VERSION 5.8 ;
BUSBITCHARS "[]" ;
DIVIDERCHAR "/" ;
UNITS
    DATABASE MICRONS 1000 ;
END UNITS

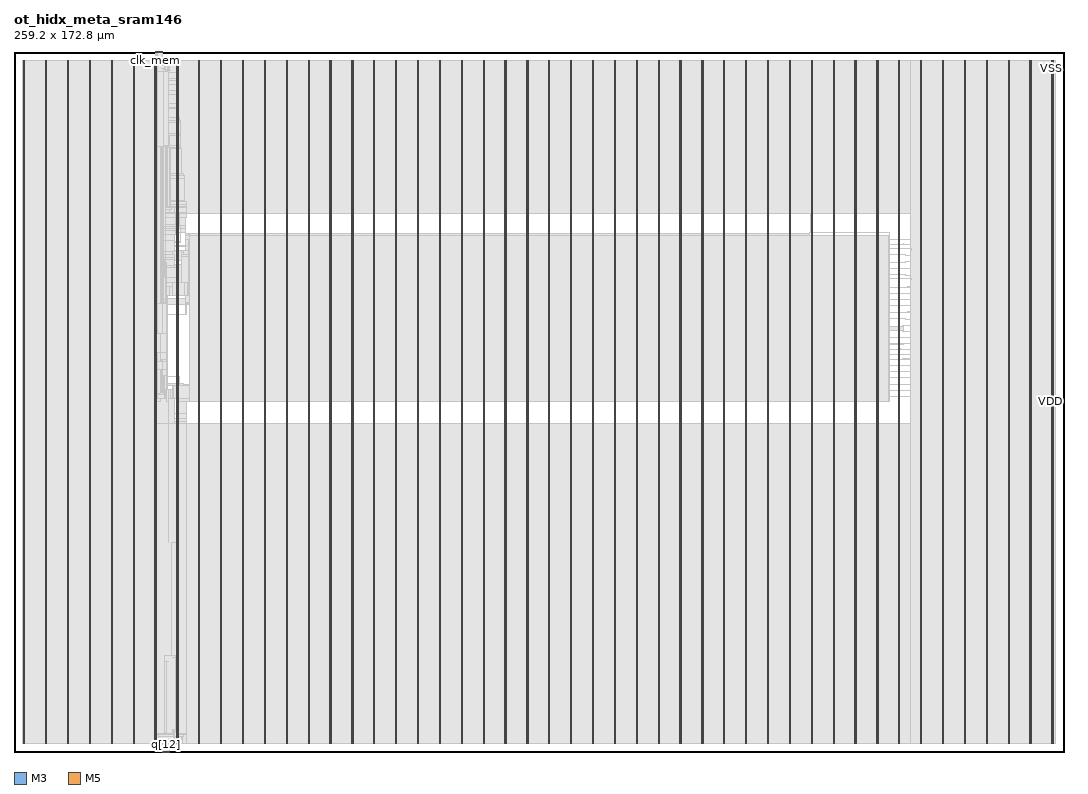
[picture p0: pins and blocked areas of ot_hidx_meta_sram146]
MACRO ot_hidx_meta_sram146
  FOREIGN ot_hidx_meta_sram146 0 0 ;
  CLASS BLOCK ;
  SIZE 259.2 BY 172.8 ;
  PIN clk
    DIRECTION INPUT ;
    USE SIGNAL ;
    PORT
      LAYER M3 ;
        RECT  34.884 172.763 34.902 172.8 ;
    END
  END clk
  PIN clk_mem
    DIRECTION INPUT ;
    USE SIGNAL ;
    PORT
      LAYER M3 ;
        RECT  34.956 172.763 34.974 172.8 ;
    END
  END clk_mem
  PIN d[0]
    DIRECTION INPUT ;
    USE SIGNAL ;
    PORT
      LAYER M3 ;
        RECT  35.028 172.763 35.046 172.8 ;
    END
  END d[0]
  PIN d[10]
    DIRECTION INPUT ;
    USE SIGNAL ;
    PORT
      LAYER M3 ;
        RECT  35.748 172.763 35.766 172.8 ;
    END
  END d[10]
  PIN d[11]
    DIRECTION INPUT ;
    USE SIGNAL ;
    PORT
      LAYER M3 ;
        RECT  35.82 172.763 35.838 172.8 ;
    END
  END d[11]
  PIN d[12]
    DIRECTION INPUT ;
    USE SIGNAL ;
    PORT
      LAYER M3 ;
        RECT  35.892 172.763 35.91 172.8 ;
    END
  END d[12]
  PIN d[13]
    DIRECTION INPUT ;
    USE SIGNAL ;
    PORT
      LAYER M3 ;
        RECT  35.964 172.763 35.982 172.8 ;
    END
  END d[13]
  PIN d[14]
    DIRECTION INPUT ;
    USE SIGNAL ;
    PORT
      LAYER M3 ;
        RECT  36.036 172.763 36.054 172.8 ;
    END
  END d[14]
  PIN d[15]
    DIRECTION INPUT ;
    USE SIGNAL ;
    PORT
      LAYER M3 ;
        RECT  36.108 172.763 36.126 172.8 ;
    END
  END d[15]
  PIN d[16]
    DIRECTION INPUT ;
    USE SIGNAL ;
    PORT
      LAYER M3 ;
        RECT  36.18 172.763 36.198 172.8 ;
    END
  END d[16]
  PIN d[17]
    DIRECTION INPUT ;
    USE SIGNAL ;
    PORT
      LAYER M3 ;
        RECT  36.252 172.763 36.27 172.8 ;
    END
  END d[17]
  PIN d[18]
    DIRECTION INPUT ;
    USE SIGNAL ;
    PORT
      LAYER M3 ;
        RECT  36.324 172.763 36.342 172.8 ;
    END
  END d[18]
  PIN d[19]
    DIRECTION INPUT ;
    USE SIGNAL ;
    PORT
      LAYER M3 ;
        RECT  36.396 172.763 36.414 172.8 ;
    END
  END d[19]
  PIN d[1]
    DIRECTION INPUT ;
    USE SIGNAL ;
    PORT
      LAYER M3 ;
        RECT  35.1 172.763 35.118 172.8 ;
    END
  END d[1]
  PIN d[20]
    DIRECTION INPUT ;
    USE SIGNAL ;
    PORT
      LAYER M3 ;
        RECT  36.468 172.763 36.486 172.8 ;
    END
  END d[20]
  PIN d[21]
    DIRECTION INPUT ;
    USE SIGNAL ;
    PORT
      LAYER M3 ;
        RECT  36.54 172.763 36.558 172.8 ;
    END
  END d[21]
  PIN d[22]
    DIRECTION INPUT ;
    USE SIGNAL ;
    PORT
      LAYER M3 ;
        RECT  36.612 172.763 36.63 172.8 ;
    END
  END d[22]
  PIN d[23]
    DIRECTION INPUT ;
    USE SIGNAL ;
    PORT
      LAYER M3 ;
        RECT  36.684 172.763 36.702 172.8 ;
    END
  END d[23]
  PIN d[24]
    DIRECTION INPUT ;
    USE SIGNAL ;
    PORT
      LAYER M3 ;
        RECT  36.756 172.763 36.774 172.8 ;
    END
  END d[24]
  PIN d[2]
    DIRECTION INPUT ;
    USE SIGNAL ;
    PORT
      LAYER M3 ;
        RECT  35.172 172.763 35.19 172.8 ;
    END
  END d[2]
  PIN d[3]
    DIRECTION INPUT ;
    USE SIGNAL ;
    PORT
      LAYER M3 ;
        RECT  35.244 172.763 35.262 172.8 ;
    END
  END d[3]
  PIN d[4]
    DIRECTION INPUT ;
    USE SIGNAL ;
    PORT
      LAYER M3 ;
        RECT  35.316 172.763 35.334 172.8 ;
    END
  END d[4]
  PIN d[5]
    DIRECTION INPUT ;
    USE SIGNAL ;
    PORT
      LAYER M3 ;
        RECT  35.388 172.763 35.406 172.8 ;
    END
  END d[5]
  PIN d[6]
    DIRECTION INPUT ;
    USE SIGNAL ;
    PORT
      LAYER M3 ;
        RECT  35.46 172.763 35.478 172.8 ;
    END
  END d[6]
  PIN d[7]
    DIRECTION INPUT ;
    USE SIGNAL ;
    PORT
      LAYER M3 ;
        RECT  35.532 172.763 35.55 172.8 ;
    END
  END d[7]
  PIN d[8]
    DIRECTION INPUT ;
    USE SIGNAL ;
    PORT
      LAYER M3 ;
        RECT  35.604 172.763 35.622 172.8 ;
    END
  END d[8]
  PIN d[9]
    DIRECTION INPUT ;
    USE SIGNAL ;
    PORT
      LAYER M3 ;
        RECT  35.676 172.763 35.694 172.8 ;
    END
  END d[9]
  PIN q[0]
    DIRECTION OUTPUT ;
    USE SIGNAL ;
    PORT
      LAYER M3 ;
        RECT  36.54 0 36.558 0.037 ;
    END
  END q[0]
  PIN q[10]
    DIRECTION OUTPUT ;
    USE SIGNAL ;
    PORT
      LAYER M3 ;
        RECT  37.26 0 37.278 0.037 ;
    END
  END q[10]
  PIN q[11]
    DIRECTION OUTPUT ;
    USE SIGNAL ;
    PORT
      LAYER M3 ;
        RECT  37.332 0 37.35 0.037 ;
    END
  END q[11]
  PIN q[12]
    DIRECTION OUTPUT ;
    USE SIGNAL ;
    PORT
      LAYER M3 ;
        RECT  37.404 0 37.422 0.037 ;
    END
  END q[12]
  PIN q[13]
    DIRECTION OUTPUT ;
    USE SIGNAL ;
    PORT
      LAYER M3 ;
        RECT  37.476 0 37.494 0.037 ;
    END
  END q[13]
  PIN q[14]
    DIRECTION OUTPUT ;
    USE SIGNAL ;
    PORT
      LAYER M3 ;
        RECT  37.548 0 37.566 0.037 ;
    END
  END q[14]
  PIN q[15]
    DIRECTION OUTPUT ;
    USE SIGNAL ;
    PORT
      LAYER M3 ;
        RECT  37.62 0 37.638 0.037 ;
    END
  END q[15]
  PIN q[16]
    DIRECTION OUTPUT ;
    USE SIGNAL ;
    PORT
      LAYER M3 ;
        RECT  37.692 0 37.71 0.037 ;
    END
  END q[16]
  PIN q[17]
    DIRECTION OUTPUT ;
    USE SIGNAL ;
    PORT
      LAYER M3 ;
        RECT  37.764 0 37.782 0.037 ;
    END
  END q[17]
  PIN q[18]
    DIRECTION OUTPUT ;
    USE SIGNAL ;
    PORT
      LAYER M3 ;
        RECT  37.836 0 37.854 0.037 ;
    END
  END q[18]
  PIN q[19]
    DIRECTION OUTPUT ;
    USE SIGNAL ;
    PORT
      LAYER M3 ;
        RECT  37.908 0 37.926 0.037 ;
    END
  END q[19]
  PIN q[1]
    DIRECTION OUTPUT ;
    USE SIGNAL ;
    PORT
      LAYER M3 ;
        RECT  36.612 0 36.63 0.037 ;
    END
  END q[1]
  PIN q[20]
    DIRECTION OUTPUT ;
    USE SIGNAL ;
    PORT
      LAYER M3 ;
        RECT  37.98 0 37.998 0.037 ;
    END
  END q[20]
  PIN q[21]
    DIRECTION OUTPUT ;
    USE SIGNAL ;
    PORT
      LAYER M3 ;
        RECT  38.052 0 38.07 0.037 ;
    END
  END q[21]
  PIN q[22]
    DIRECTION OUTPUT ;
    USE SIGNAL ;
    PORT
      LAYER M3 ;
        RECT  38.124 0 38.142 0.037 ;
    END
  END q[22]
  PIN q[23]
    DIRECTION OUTPUT ;
    USE SIGNAL ;
    PORT
      LAYER M3 ;
        RECT  38.196 0 38.214 0.037 ;
    END
  END q[23]
  PIN q[24]
    DIRECTION OUTPUT ;
    USE SIGNAL ;
    PORT
      LAYER M3 ;
        RECT  38.268 0 38.286 0.037 ;
    END
  END q[24]
  PIN q[2]
    DIRECTION OUTPUT ;
    USE SIGNAL ;
    PORT
      LAYER M3 ;
        RECT  36.684 0 36.702 0.037 ;
    END
  END q[2]
  PIN q[3]
    DIRECTION OUTPUT ;
    USE SIGNAL ;
    PORT
      LAYER M3 ;
        RECT  36.756 0 36.774 0.037 ;
    END
  END q[3]
  PIN q[4]
    DIRECTION OUTPUT ;
    USE SIGNAL ;
    PORT
      LAYER M3 ;
        RECT  36.828 0 36.846 0.037 ;
    END
  END q[4]
  PIN q[5]
    DIRECTION OUTPUT ;
    USE SIGNAL ;
    PORT
      LAYER M3 ;
        RECT  36.9 0 36.918 0.037 ;
    END
  END q[5]
  PIN q[6]
    DIRECTION OUTPUT ;
    USE SIGNAL ;
    PORT
      LAYER M3 ;
        RECT  36.972 0 36.99 0.037 ;
    END
  END q[6]
  PIN q[7]
    DIRECTION OUTPUT ;
    USE SIGNAL ;
    PORT
      LAYER M3 ;
        RECT  37.044 0 37.062 0.037 ;
    END
  END q[7]
  PIN q[8]
    DIRECTION OUTPUT ;
    USE SIGNAL ;
    PORT
      LAYER M3 ;
        RECT  37.116 0 37.134 0.037 ;
    END
  END q[8]
  PIN q[9]
    DIRECTION OUTPUT ;
    USE SIGNAL ;
    PORT
      LAYER M3 ;
        RECT  37.188 0 37.206 0.037 ;
    END
  END q[9]
  PIN VDD
    DIRECTION INOUT ;
    USE POWER ;
    PORT
      LAYER M5 ;
        RECT  256.392 2.151 256.512 170.649 ;
        RECT  250.992 2.151 251.112 170.649 ;
        RECT  245.592 2.151 245.712 170.649 ;
        RECT  240.192 2.151 240.312 170.649 ;
        RECT  234.792 2.151 234.912 170.649 ;
        RECT  229.392 2.151 229.512 170.649 ;
        RECT  223.992 2.151 224.112 170.649 ;
        RECT  218.592 2.151 218.712 170.649 ;
        RECT  213.192 2.151 213.312 170.649 ;
        RECT  207.792 2.151 207.912 170.649 ;
        RECT  202.392 2.151 202.512 170.649 ;
        RECT  196.992 2.151 197.112 170.649 ;
        RECT  191.592 2.151 191.712 170.649 ;
        RECT  186.192 2.151 186.312 170.649 ;
        RECT  180.792 2.151 180.912 170.649 ;
        RECT  175.392 2.151 175.512 170.649 ;
        RECT  169.992 2.151 170.112 170.649 ;
        RECT  164.592 2.151 164.712 170.649 ;
        RECT  159.192 2.151 159.312 170.649 ;
        RECT  153.792 2.151 153.912 170.649 ;
        RECT  148.392 2.151 148.512 170.649 ;
        RECT  142.992 2.151 143.112 170.649 ;
        RECT  137.592 2.151 137.712 170.649 ;
        RECT  132.192 2.151 132.312 170.649 ;
        RECT  126.792 2.151 126.912 170.649 ;
        RECT  121.392 2.151 121.512 170.649 ;
        RECT  115.992 2.151 116.112 170.649 ;
        RECT  110.592 2.151 110.712 170.649 ;
        RECT  105.192 2.151 105.312 170.649 ;
        RECT  99.792 2.151 99.912 170.649 ;
        RECT  94.392 2.151 94.512 170.649 ;
        RECT  88.992 2.151 89.112 170.649 ;
        RECT  83.592 2.151 83.712 170.649 ;
        RECT  78.192 2.151 78.312 170.649 ;
        RECT  72.792 2.151 72.912 170.649 ;
        RECT  67.392 2.151 67.512 170.649 ;
        RECT  61.992 2.151 62.112 170.649 ;
        RECT  56.592 2.151 56.712 170.649 ;
        RECT  51.192 2.151 51.312 170.649 ;
        RECT  45.792 2.151 45.912 170.649 ;
        RECT  40.392 2.151 40.512 170.649 ;
        RECT  34.992 2.151 35.112 170.649 ;
        RECT  29.592 2.151 29.712 170.649 ;
        RECT  24.192 2.151 24.312 170.649 ;
        RECT  18.792 2.151 18.912 170.649 ;
        RECT  13.392 2.151 13.512 170.649 ;
        RECT  7.992 2.151 8.112 170.649 ;
        RECT  2.592 2.151 2.712 170.649 ;
    END
  END VDD
  PIN VSS
    DIRECTION INOUT ;
    USE GROUND ;
    PORT
      LAYER M5 ;
        RECT  256.2 2.137 256.32 170.663 ;
        RECT  250.8 2.137 250.92 170.663 ;
        RECT  245.4 2.137 245.52 170.663 ;
        RECT  240 2.137 240.12 170.663 ;
        RECT  234.6 2.137 234.72 170.663 ;
        RECT  229.2 2.137 229.32 170.663 ;
        RECT  223.8 2.137 223.92 170.663 ;
        RECT  218.4 2.137 218.52 170.663 ;
        RECT  213 2.137 213.12 170.663 ;
        RECT  207.6 2.137 207.72 170.663 ;
        RECT  202.2 2.137 202.32 170.663 ;
        RECT  196.8 2.137 196.92 170.663 ;
        RECT  191.4 2.137 191.52 170.663 ;
        RECT  186 2.137 186.12 170.663 ;
        RECT  180.6 2.137 180.72 170.663 ;
        RECT  175.2 2.137 175.32 170.663 ;
        RECT  169.8 2.137 169.92 170.663 ;
        RECT  164.4 2.137 164.52 170.663 ;
        RECT  159 2.137 159.12 170.663 ;
        RECT  153.6 2.137 153.72 170.663 ;
        RECT  148.2 2.137 148.32 170.663 ;
        RECT  142.8 2.137 142.92 170.663 ;
        RECT  137.4 2.137 137.52 170.663 ;
        RECT  132 2.137 132.12 170.663 ;
        RECT  126.6 2.137 126.72 170.663 ;
        RECT  121.2 2.137 121.32 170.663 ;
        RECT  115.8 2.137 115.92 170.663 ;
        RECT  110.4 2.137 110.52 170.663 ;
        RECT  105 2.137 105.12 170.663 ;
        RECT  99.6 2.137 99.72 170.663 ;
        RECT  94.2 2.137 94.32 170.663 ;
        RECT  88.8 2.137 88.92 170.663 ;
        RECT  83.4 2.137 83.52 170.663 ;
        RECT  78 2.137 78.12 170.663 ;
        RECT  72.6 2.137 72.72 170.663 ;
        RECT  67.2 2.137 67.32 170.663 ;
        RECT  61.8 2.137 61.92 170.663 ;
        RECT  56.4 2.137 56.52 170.663 ;
        RECT  51 2.137 51.12 170.663 ;
        RECT  45.6 2.137 45.72 170.663 ;
        RECT  40.2 2.137 40.32 170.663 ;
        RECT  34.8 2.137 34.92 170.663 ;
        RECT  29.4 2.137 29.52 170.663 ;
        RECT  24 2.137 24.12 170.663 ;
        RECT  18.6 2.137 18.72 170.663 ;
        RECT  13.2 2.137 13.32 170.663 ;
        RECT  7.8 2.137 7.92 170.663 ;
        RECT  2.4 2.137 2.52 170.663 ;
    END
  END VSS
  # OT_OBS_CLOSED layer=M5 d_um=1.536 added=8
  OBS
    LAYER RVTN ;
     RECT  2.16 2.16 257.04 2.295 ;
     RECT  2.16 2.565 257.04 2.835 ;
     RECT  2.16 3.105 257.04 3.375 ;
     RECT  2.16 3.645 257.04 3.915 ;
     RECT  2.16 4.185 257.04 4.455 ;
     RECT  2.16 4.725 257.04 4.995 ;
     RECT  2.16 5.265 257.04 5.535 ;
     RECT  2.16 5.805 257.04 6.075 ;
     RECT  2.16 6.345 257.04 6.615 ;
     RECT  2.16 6.885 257.04 7.155 ;
     RECT  2.16 7.425 257.04 7.695 ;
     RECT  2.16 7.965 257.04 8.235 ;
     RECT  2.16 8.505 257.04 8.775 ;
     RECT  2.16 9.045 257.04 9.315 ;
     RECT  2.16 9.585 257.04 9.855 ;
     RECT  2.16 10.125 257.04 10.395 ;
     RECT  2.16 10.665 257.04 10.935 ;
     RECT  2.16 11.205 257.04 11.475 ;
     RECT  2.16 11.745 257.04 12.015 ;
     RECT  2.16 12.285 257.04 12.555 ;
     RECT  2.16 12.825 257.04 13.095 ;
     RECT  2.16 13.365 257.04 13.635 ;
     RECT  2.16 13.905 257.04 14.175 ;
     RECT  2.16 14.445 257.04 14.715 ;
     RECT  2.16 14.985 257.04 15.255 ;
     RECT  2.16 15.525 257.04 15.795 ;
     RECT  2.16 16.065 257.04 16.335 ;
     RECT  2.16 16.605 257.04 16.875 ;
     RECT  2.16 17.145 257.04 17.415 ;
     RECT  2.16 17.685 257.04 17.955 ;
     RECT  2.16 18.225 257.04 18.495 ;
     RECT  2.16 18.765 257.04 19.035 ;
     RECT  2.16 19.305 257.04 19.575 ;
     RECT  2.16 19.845 257.04 20.115 ;
     RECT  2.16 20.385 257.04 20.655 ;
     RECT  2.16 20.925 257.04 21.195 ;
     RECT  2.16 21.465 257.04 21.735 ;
     RECT  2.16 22.005 257.04 22.275 ;
     RECT  2.16 22.545 257.04 22.815 ;
     RECT  2.16 23.085 257.04 23.355 ;
     RECT  2.16 23.625 257.04 23.895 ;
     RECT  2.16 24.165 257.04 24.435 ;
     RECT  2.16 24.705 257.04 24.975 ;
     RECT  2.16 25.245 257.04 25.515 ;
     RECT  2.16 25.785 257.04 26.055 ;
     RECT  2.16 26.325 257.04 26.595 ;
     RECT  2.16 26.865 257.04 27.135 ;
     RECT  2.16 27.405 257.04 27.675 ;
     RECT  2.16 27.945 257.04 28.215 ;
     RECT  2.16 28.485 257.04 28.755 ;
     RECT  2.16 29.025 257.04 29.295 ;
     RECT  2.16 29.565 257.04 29.835 ;
     RECT  2.16 30.105 257.04 30.375 ;
     RECT  2.16 30.645 257.04 30.915 ;
     RECT  2.16 31.185 257.04 31.455 ;
     RECT  2.16 31.725 257.04 31.995 ;
     RECT  2.16 32.265 257.04 32.535 ;
     RECT  2.16 32.805 257.04 33.075 ;
     RECT  2.16 33.345 257.04 33.615 ;
     RECT  2.16 33.885 257.04 34.155 ;
     RECT  2.16 34.425 257.04 34.695 ;
     RECT  2.16 34.965 257.04 35.235 ;
     RECT  2.16 35.505 257.04 35.775 ;
     RECT  2.16 36.045 257.04 36.315 ;
     RECT  2.16 36.585 257.04 36.855 ;
     RECT  2.16 37.125 257.04 37.395 ;
     RECT  2.16 37.665 257.04 37.935 ;
     RECT  2.16 38.205 257.04 38.475 ;
     RECT  2.16 38.745 257.04 39.015 ;
     RECT  2.16 39.285 257.04 39.555 ;
     RECT  2.16 39.825 257.04 40.095 ;
     RECT  2.16 40.365 257.04 40.635 ;
     RECT  2.16 40.905 257.04 41.175 ;
     RECT  2.16 41.445 257.04 41.715 ;
     RECT  2.16 41.985 257.04 42.255 ;
     RECT  2.16 42.525 257.04 42.795 ;
     RECT  2.16 43.065 257.04 43.335 ;
     RECT  2.16 43.605 257.04 43.875 ;
     RECT  2.16 44.145 257.04 44.415 ;
     RECT  2.16 44.685 257.04 44.955 ;
     RECT  2.16 45.225 257.04 45.495 ;
     RECT  2.16 45.765 257.04 46.035 ;
     RECT  2.16 46.305 257.04 46.575 ;
     RECT  2.16 46.845 257.04 47.115 ;
     RECT  2.16 47.385 257.04 47.655 ;
     RECT  2.16 47.925 257.04 48.195 ;
     RECT  2.16 48.465 257.04 48.735 ;
     RECT  2.16 49.005 257.04 49.275 ;
     RECT  2.16 49.545 257.04 49.815 ;
     RECT  2.16 50.085 257.04 50.355 ;
     RECT  2.16 50.625 257.04 50.895 ;
     RECT  2.16 51.165 257.04 51.435 ;
     RECT  2.16 51.705 257.04 51.975 ;
     RECT  2.16 52.245 257.04 52.515 ;
     RECT  2.16 52.785 257.04 53.055 ;
     RECT  2.16 53.325 257.04 53.595 ;
     RECT  2.16 53.865 257.04 54.135 ;
     RECT  2.16 54.405 257.04 54.675 ;
     RECT  2.16 54.945 257.04 55.215 ;
     RECT  2.16 55.485 257.04 55.755 ;
     RECT  2.16 56.025 257.04 56.295 ;
     RECT  2.16 56.565 257.04 56.835 ;
     RECT  2.16 57.105 257.04 57.375 ;
     RECT  2.16 57.645 257.04 57.915 ;
     RECT  2.16 58.185 257.04 58.455 ;
     RECT  2.16 58.725 257.04 58.995 ;
     RECT  2.16 59.265 257.04 59.535 ;
     RECT  2.16 59.805 257.04 60.075 ;
     RECT  2.16 60.345 257.04 60.615 ;
     RECT  2.16 60.885 257.04 61.155 ;
     RECT  2.16 61.425 257.04 61.695 ;
     RECT  2.16 61.965 257.04 62.235 ;
     RECT  2.16 62.505 257.04 62.775 ;
     RECT  2.16 63.045 257.04 63.315 ;
     RECT  2.16 63.585 257.04 63.855 ;
     RECT  2.16 64.125 257.04 64.395 ;
     RECT  2.16 64.665 257.04 64.935 ;
     RECT  2.16 65.205 257.04 65.475 ;
     RECT  2.16 65.745 257.04 66.015 ;
     RECT  2.16 66.285 257.04 66.555 ;
     RECT  2.16 66.825 257.04 67.095 ;
     RECT  2.16 67.365 257.04 67.635 ;
     RECT  2.16 67.905 257.04 68.175 ;
     RECT  2.16 68.445 257.04 68.715 ;
     RECT  2.16 68.985 257.04 69.255 ;
     RECT  2.16 69.525 257.04 69.795 ;
     RECT  2.16 70.065 257.04 70.335 ;
     RECT  2.16 70.605 257.04 70.875 ;
     RECT  2.16 71.145 257.04 71.415 ;
     RECT  2.16 71.685 257.04 71.955 ;
     RECT  2.16 72.225 257.04 72.495 ;
     RECT  2.16 72.765 257.04 73.035 ;
     RECT  2.16 73.305 257.04 73.575 ;
     RECT  2.16 73.845 257.04 74.115 ;
     RECT  2.16 74.385 257.04 74.655 ;
     RECT  2.16 74.925 257.04 75.195 ;
     RECT  2.16 75.465 257.04 75.735 ;
     RECT  2.16 76.005 257.04 76.275 ;
     RECT  2.16 76.545 257.04 76.815 ;
     RECT  2.16 77.085 257.04 77.355 ;
     RECT  2.16 77.625 257.04 77.895 ;
     RECT  2.16 78.165 257.04 78.435 ;
     RECT  2.16 78.705 257.04 78.975 ;
     RECT  2.16 79.245 257.04 79.515 ;
     RECT  2.16 79.785 257.04 80.055 ;
     RECT  2.16 80.325 257.04 80.595 ;
     RECT  2.16 80.865 257.04 81 ;
     RECT  2.16 81 37.8 81.135 ;
     RECT  221.4 81 257.04 81.135 ;
     RECT  2.16 81.405 37.8 81.675 ;
     RECT  221.4 81.405 257.04 81.675 ;
     RECT  2.16 81.945 37.8 82.215 ;
     RECT  221.4 81.945 257.04 82.215 ;
     RECT  2.16 82.485 37.8 82.755 ;
     RECT  221.4 82.485 257.04 82.755 ;
     RECT  2.16 83.025 37.8 83.295 ;
     RECT  221.4 83.025 257.04 83.295 ;
     RECT  2.16 83.565 37.8 83.835 ;
     RECT  221.4 83.565 257.04 83.835 ;
     RECT  2.16 84.105 37.8 84.375 ;
     RECT  221.4 84.105 257.04 84.375 ;
     RECT  2.16 84.645 37.8 84.915 ;
     RECT  221.4 84.645 257.04 84.915 ;
     RECT  2.16 85.185 37.8 85.455 ;
     RECT  221.4 85.185 257.04 85.455 ;
     RECT  2.16 85.725 37.8 85.995 ;
     RECT  221.4 85.725 257.04 85.995 ;
     RECT  2.16 86.265 37.8 86.535 ;
     RECT  221.4 86.265 257.04 86.535 ;
     RECT  2.16 86.805 37.8 87.075 ;
     RECT  221.4 86.805 257.04 87.075 ;
     RECT  2.16 87.345 37.8 87.615 ;
     RECT  221.4 87.345 257.04 87.615 ;
     RECT  2.16 87.885 37.8 88.155 ;
     RECT  221.4 87.885 257.04 88.155 ;
     RECT  2.16 88.425 37.8 88.695 ;
     RECT  221.4 88.425 257.04 88.695 ;
     RECT  2.16 88.965 37.8 89.235 ;
     RECT  221.4 88.965 257.04 89.235 ;
     RECT  2.16 89.505 37.8 89.775 ;
     RECT  221.4 89.505 257.04 89.775 ;
     RECT  2.16 90.045 37.8 90.315 ;
     RECT  221.4 90.045 257.04 90.315 ;
     RECT  2.16 90.585 37.8 90.855 ;
     RECT  221.4 90.585 257.04 90.855 ;
     RECT  2.16 91.125 37.8 91.395 ;
     RECT  221.4 91.125 257.04 91.395 ;
     RECT  2.16 91.665 37.8 91.935 ;
     RECT  221.4 91.665 257.04 91.935 ;
     RECT  2.16 92.205 37.8 92.475 ;
     RECT  221.4 92.205 257.04 92.475 ;
     RECT  2.16 92.745 37.8 93.015 ;
     RECT  221.4 92.745 257.04 93.015 ;
     RECT  2.16 93.285 37.8 93.555 ;
     RECT  221.4 93.285 257.04 93.555 ;
     RECT  2.16 93.825 37.8 94.095 ;
     RECT  221.4 93.825 257.04 94.095 ;
     RECT  2.16 94.365 37.8 94.635 ;
     RECT  221.4 94.365 257.04 94.635 ;
     RECT  2.16 94.905 37.8 95.175 ;
     RECT  221.4 94.905 257.04 95.175 ;
     RECT  2.16 95.445 37.8 95.715 ;
     RECT  221.4 95.445 257.04 95.715 ;
     RECT  2.16 95.985 37.8 96.255 ;
     RECT  221.4 95.985 257.04 96.255 ;
     RECT  2.16 96.525 37.8 96.795 ;
     RECT  221.4 96.525 257.04 96.795 ;
     RECT  2.16 97.065 37.8 97.335 ;
     RECT  221.4 97.065 257.04 97.335 ;
     RECT  2.16 97.605 37.8 97.875 ;
     RECT  221.4 97.605 257.04 97.875 ;
     RECT  2.16 98.145 37.8 98.415 ;
     RECT  221.4 98.145 257.04 98.415 ;
     RECT  2.16 98.685 37.8 98.955 ;
     RECT  221.4 98.685 257.04 98.955 ;
     RECT  2.16 99.225 37.8 99.495 ;
     RECT  221.4 99.225 257.04 99.495 ;
     RECT  2.16 99.765 37.8 100.035 ;
     RECT  221.4 99.765 257.04 100.035 ;
     RECT  2.16 100.305 37.8 100.575 ;
     RECT  221.4 100.305 257.04 100.575 ;
     RECT  2.16 100.845 37.8 101.115 ;
     RECT  221.4 100.845 257.04 101.115 ;
     RECT  2.16 101.385 37.8 101.655 ;
     RECT  221.4 101.385 257.04 101.655 ;
     RECT  2.16 101.925 37.8 102.195 ;
     RECT  221.4 101.925 257.04 102.195 ;
     RECT  2.16 102.465 37.8 102.735 ;
     RECT  221.4 102.465 257.04 102.735 ;
     RECT  2.16 103.005 37.8 103.275 ;
     RECT  221.4 103.005 257.04 103.275 ;
     RECT  2.16 103.545 37.8 103.815 ;
     RECT  221.4 103.545 257.04 103.815 ;
     RECT  2.16 104.085 37.8 104.355 ;
     RECT  221.4 104.085 257.04 104.355 ;
     RECT  2.16 104.625 37.8 104.895 ;
     RECT  221.4 104.625 257.04 104.895 ;
     RECT  2.16 105.165 37.8 105.435 ;
     RECT  221.4 105.165 257.04 105.435 ;
     RECT  2.16 105.705 37.8 105.975 ;
     RECT  221.4 105.705 257.04 105.975 ;
     RECT  2.16 106.245 37.8 106.515 ;
     RECT  221.4 106.245 257.04 106.515 ;
     RECT  2.16 106.785 37.8 107.055 ;
     RECT  221.4 106.785 257.04 107.055 ;
     RECT  2.16 107.325 37.8 107.595 ;
     RECT  221.4 107.325 257.04 107.595 ;
     RECT  2.16 107.865 37.8 108.135 ;
     RECT  221.4 107.865 257.04 108.135 ;
     RECT  2.16 108.405 37.8 108.675 ;
     RECT  221.4 108.405 257.04 108.675 ;
     RECT  2.16 108.945 37.8 109.215 ;
     RECT  221.4 108.945 257.04 109.215 ;
     RECT  2.16 109.485 37.8 109.755 ;
     RECT  221.4 109.485 257.04 109.755 ;
     RECT  2.16 110.025 37.8 110.295 ;
     RECT  221.4 110.025 257.04 110.295 ;
     RECT  2.16 110.565 37.8 110.835 ;
     RECT  221.4 110.565 257.04 110.835 ;
     RECT  2.16 111.105 37.8 111.375 ;
     RECT  221.4 111.105 257.04 111.375 ;
     RECT  2.16 111.645 37.8 111.915 ;
     RECT  221.4 111.645 257.04 111.915 ;
     RECT  2.16 112.185 37.8 112.455 ;
     RECT  221.4 112.185 257.04 112.455 ;
     RECT  2.16 112.725 37.8 112.995 ;
     RECT  221.4 112.725 257.04 112.995 ;
     RECT  2.16 113.265 37.8 113.535 ;
     RECT  221.4 113.265 257.04 113.535 ;
     RECT  2.16 113.805 37.8 114.075 ;
     RECT  221.4 113.805 257.04 114.075 ;
     RECT  2.16 114.345 37.8 114.615 ;
     RECT  221.4 114.345 257.04 114.615 ;
     RECT  2.16 114.885 37.8 115.155 ;
     RECT  221.4 114.885 257.04 115.155 ;
     RECT  2.16 115.425 37.8 115.695 ;
     RECT  221.4 115.425 257.04 115.695 ;
     RECT  2.16 115.965 37.8 116.235 ;
     RECT  221.4 115.965 257.04 116.235 ;
     RECT  2.16 116.505 37.8 116.775 ;
     RECT  221.4 116.505 257.04 116.775 ;
     RECT  2.16 117.045 37.8 117.315 ;
     RECT  221.4 117.045 257.04 117.315 ;
     RECT  2.16 117.585 37.8 117.855 ;
     RECT  221.4 117.585 257.04 117.855 ;
     RECT  2.16 118.125 37.8 118.395 ;
     RECT  221.4 118.125 257.04 118.395 ;
     RECT  2.16 118.665 37.8 118.935 ;
     RECT  221.4 118.665 257.04 118.935 ;
     RECT  2.16 119.205 37.8 119.475 ;
     RECT  221.4 119.205 257.04 119.475 ;
     RECT  2.16 119.745 37.8 120.015 ;
     RECT  221.4 119.745 257.04 120.015 ;
     RECT  2.16 120.285 37.8 120.555 ;
     RECT  221.4 120.285 257.04 120.555 ;
     RECT  2.16 120.825 37.8 121.095 ;
     RECT  221.4 120.825 257.04 121.095 ;
     RECT  2.16 121.365 37.8 121.635 ;
     RECT  221.4 121.365 257.04 121.635 ;
     RECT  2.16 121.905 37.8 122.175 ;
     RECT  221.4 121.905 257.04 122.175 ;
     RECT  2.16 122.445 37.8 122.715 ;
     RECT  221.4 122.445 257.04 122.715 ;
     RECT  2.16 122.985 37.8 123.255 ;
     RECT  221.4 122.985 257.04 123.255 ;
     RECT  2.16 123.525 37.8 123.795 ;
     RECT  221.4 123.525 257.04 123.795 ;
     RECT  2.16 124.065 37.8 124.335 ;
     RECT  221.4 124.065 257.04 124.335 ;
     RECT  2.16 124.605 37.8 124.875 ;
     RECT  221.4 124.605 257.04 124.875 ;
     RECT  2.16 125.145 37.8 125.415 ;
     RECT  221.4 125.145 257.04 125.415 ;
     RECT  2.16 125.685 37.8 125.955 ;
     RECT  221.4 125.685 257.04 125.955 ;
     RECT  2.16 126.225 37.8 126.495 ;
     RECT  221.4 126.225 257.04 126.495 ;
     RECT  2.16 126.765 37.8 127.035 ;
     RECT  221.4 126.765 257.04 127.035 ;
     RECT  2.16 127.305 37.8 127.575 ;
     RECT  221.4 127.305 257.04 127.575 ;
     RECT  2.16 127.845 37.8 128.115 ;
     RECT  221.4 127.845 257.04 128.115 ;
     RECT  2.16 128.385 37.8 128.655 ;
     RECT  221.4 128.385 257.04 128.655 ;
     RECT  2.16 128.925 37.8 129.195 ;
     RECT  221.4 128.925 257.04 129.195 ;
     RECT  2.16 129.465 37.8 129.735 ;
     RECT  221.4 129.465 257.04 129.735 ;
     RECT  2.16 130.005 37.8 130.275 ;
     RECT  221.4 130.005 257.04 130.275 ;
     RECT  2.16 130.545 37.8 130.815 ;
     RECT  221.4 130.545 257.04 130.815 ;
     RECT  2.16 131.085 37.8 131.355 ;
     RECT  221.4 131.085 257.04 131.355 ;
     RECT  2.16 131.625 37.8 131.895 ;
     RECT  221.4 131.625 257.04 131.895 ;
     RECT  2.16 132.165 37.8 132.435 ;
     RECT  221.4 132.165 257.04 132.435 ;
     RECT  2.16 132.705 37.8 132.84 ;
     RECT  221.4 132.705 257.04 132.84 ;
     RECT  2.16 132.84 257.04 132.975 ;
     RECT  2.16 133.245 257.04 133.515 ;
     RECT  2.16 133.785 257.04 134.055 ;
     RECT  2.16 134.325 257.04 134.595 ;
     RECT  2.16 134.865 257.04 135.135 ;
     RECT  2.16 135.405 257.04 135.675 ;
     RECT  2.16 135.945 257.04 136.215 ;
     RECT  2.16 136.485 257.04 136.755 ;
     RECT  2.16 137.025 257.04 137.295 ;
     RECT  2.16 137.565 257.04 137.835 ;
     RECT  2.16 138.105 257.04 138.375 ;
     RECT  2.16 138.645 257.04 138.915 ;
     RECT  2.16 139.185 257.04 139.455 ;
     RECT  2.16 139.725 257.04 139.995 ;
     RECT  2.16 140.265 257.04 140.535 ;
     RECT  2.16 140.805 257.04 141.075 ;
     RECT  2.16 141.345 257.04 141.615 ;
     RECT  2.16 141.885 257.04 142.155 ;
     RECT  2.16 142.425 257.04 142.695 ;
     RECT  2.16 142.965 257.04 143.235 ;
     RECT  2.16 143.505 257.04 143.775 ;
     RECT  2.16 144.045 257.04 144.315 ;
     RECT  2.16 144.585 257.04 144.855 ;
     RECT  2.16 145.125 257.04 145.395 ;
     RECT  2.16 145.665 257.04 145.935 ;
     RECT  2.16 146.205 257.04 146.475 ;
     RECT  2.16 146.745 257.04 147.015 ;
     RECT  2.16 147.285 257.04 147.555 ;
     RECT  2.16 147.825 257.04 148.095 ;
     RECT  2.16 148.365 257.04 148.635 ;
     RECT  2.16 148.905 257.04 149.175 ;
     RECT  2.16 149.445 257.04 149.715 ;
     RECT  2.16 149.985 257.04 150.255 ;
     RECT  2.16 150.525 257.04 150.795 ;
     RECT  2.16 151.065 257.04 151.335 ;
     RECT  2.16 151.605 257.04 151.875 ;
     RECT  2.16 152.145 257.04 152.415 ;
     RECT  2.16 152.685 257.04 152.955 ;
     RECT  2.16 153.225 257.04 153.495 ;
     RECT  2.16 153.765 257.04 154.035 ;
     RECT  2.16 154.305 257.04 154.575 ;
     RECT  2.16 154.845 257.04 155.115 ;
     RECT  2.16 155.385 257.04 155.655 ;
     RECT  2.16 155.925 257.04 156.195 ;
     RECT  2.16 156.465 257.04 156.735 ;
     RECT  2.16 157.005 257.04 157.275 ;
     RECT  2.16 157.545 257.04 157.815 ;
     RECT  2.16 158.085 257.04 158.355 ;
     RECT  2.16 158.625 257.04 158.895 ;
     RECT  2.16 159.165 257.04 159.435 ;
     RECT  2.16 159.705 257.04 159.975 ;
     RECT  2.16 160.245 257.04 160.515 ;
     RECT  2.16 160.785 257.04 161.055 ;
     RECT  2.16 161.325 257.04 161.595 ;
     RECT  2.16 161.865 257.04 162.135 ;
     RECT  2.16 162.405 257.04 162.675 ;
     RECT  2.16 162.945 257.04 163.215 ;
     RECT  2.16 163.485 257.04 163.755 ;
     RECT  2.16 164.025 257.04 164.295 ;
     RECT  2.16 164.565 257.04 164.835 ;
     RECT  2.16 165.105 257.04 165.375 ;
     RECT  2.16 165.645 257.04 165.915 ;
     RECT  2.16 166.185 257.04 166.455 ;
     RECT  2.16 166.725 257.04 166.995 ;
     RECT  2.16 167.265 257.04 167.535 ;
     RECT  2.16 167.805 257.04 168.075 ;
     RECT  2.16 168.345 257.04 168.615 ;
     RECT  2.16 168.885 257.04 169.155 ;
     RECT  2.16 169.425 257.04 169.695 ;
     RECT  2.16 169.965 257.04 170.235 ;
     RECT  2.16 170.505 257.04 170.64 ;
    LAYER RVTP ;
     RECT  2.16 2.295 257.04 2.565 ;
     RECT  2.16 2.835 257.04 3.105 ;
     RECT  2.16 3.375 257.04 3.645 ;
     RECT  2.16 3.915 257.04 4.185 ;
     RECT  2.16 4.455 257.04 4.725 ;
     RECT  2.16 4.995 257.04 5.265 ;
     RECT  2.16 5.535 257.04 5.805 ;
     RECT  2.16 6.075 257.04 6.345 ;
     RECT  2.16 6.615 257.04 6.885 ;
     RECT  2.16 7.155 257.04 7.425 ;
     RECT  2.16 7.695 257.04 7.965 ;
     RECT  2.16 8.235 257.04 8.505 ;
     RECT  2.16 8.775 257.04 9.045 ;
     RECT  2.16 9.315 257.04 9.585 ;
     RECT  2.16 9.855 257.04 10.125 ;
     RECT  2.16 10.395 257.04 10.665 ;
     RECT  2.16 10.935 257.04 11.205 ;
     RECT  2.16 11.475 257.04 11.745 ;
     RECT  2.16 12.015 257.04 12.285 ;
     RECT  2.16 12.555 257.04 12.825 ;
     RECT  2.16 13.095 257.04 13.365 ;
     RECT  2.16 13.635 257.04 13.905 ;
     RECT  2.16 14.175 257.04 14.445 ;
     RECT  2.16 14.715 257.04 14.985 ;
     RECT  2.16 15.255 257.04 15.525 ;
     RECT  2.16 15.795 257.04 16.065 ;
     RECT  2.16 16.335 257.04 16.605 ;
     RECT  2.16 16.875 257.04 17.145 ;
     RECT  2.16 17.415 257.04 17.685 ;
     RECT  2.16 17.955 257.04 18.225 ;
     RECT  2.16 18.495 257.04 18.765 ;
     RECT  2.16 19.035 257.04 19.305 ;
     RECT  2.16 19.575 257.04 19.845 ;
     RECT  2.16 20.115 257.04 20.385 ;
     RECT  2.16 20.655 257.04 20.925 ;
     RECT  2.16 21.195 257.04 21.465 ;
     RECT  2.16 21.735 257.04 22.005 ;
     RECT  2.16 22.275 257.04 22.545 ;
     RECT  2.16 22.815 257.04 23.085 ;
     RECT  2.16 23.355 257.04 23.625 ;
     RECT  2.16 23.895 257.04 24.165 ;
     RECT  2.16 24.435 257.04 24.705 ;
     RECT  2.16 24.975 257.04 25.245 ;
     RECT  2.16 25.515 257.04 25.785 ;
     RECT  2.16 26.055 257.04 26.325 ;
     RECT  2.16 26.595 257.04 26.865 ;
     RECT  2.16 27.135 257.04 27.405 ;
     RECT  2.16 27.675 257.04 27.945 ;
     RECT  2.16 28.215 257.04 28.485 ;
     RECT  2.16 28.755 257.04 29.025 ;
     RECT  2.16 29.295 257.04 29.565 ;
     RECT  2.16 29.835 257.04 30.105 ;
     RECT  2.16 30.375 257.04 30.645 ;
     RECT  2.16 30.915 257.04 31.185 ;
     RECT  2.16 31.455 257.04 31.725 ;
     RECT  2.16 31.995 257.04 32.265 ;
     RECT  2.16 32.535 257.04 32.805 ;
     RECT  2.16 33.075 257.04 33.345 ;
     RECT  2.16 33.615 257.04 33.885 ;
     RECT  2.16 34.155 257.04 34.425 ;
     RECT  2.16 34.695 257.04 34.965 ;
     RECT  2.16 35.235 257.04 35.505 ;
     RECT  2.16 35.775 257.04 36.045 ;
     RECT  2.16 36.315 257.04 36.585 ;
     RECT  2.16 36.855 257.04 37.125 ;
     RECT  2.16 37.395 257.04 37.665 ;
     RECT  2.16 37.935 257.04 38.205 ;
     RECT  2.16 38.475 257.04 38.745 ;
     RECT  2.16 39.015 257.04 39.285 ;
     RECT  2.16 39.555 257.04 39.825 ;
     RECT  2.16 40.095 257.04 40.365 ;
     RECT  2.16 40.635 257.04 40.905 ;
     RECT  2.16 41.175 257.04 41.445 ;
     RECT  2.16 41.715 257.04 41.985 ;
     RECT  2.16 42.255 257.04 42.525 ;
     RECT  2.16 42.795 257.04 43.065 ;
     RECT  2.16 43.335 257.04 43.605 ;
     RECT  2.16 43.875 257.04 44.145 ;
     RECT  2.16 44.415 257.04 44.685 ;
     RECT  2.16 44.955 257.04 45.225 ;
     RECT  2.16 45.495 257.04 45.765 ;
     RECT  2.16 46.035 257.04 46.305 ;
     RECT  2.16 46.575 257.04 46.845 ;
     RECT  2.16 47.115 257.04 47.385 ;
     RECT  2.16 47.655 257.04 47.925 ;
     RECT  2.16 48.195 257.04 48.465 ;
     RECT  2.16 48.735 257.04 49.005 ;
     RECT  2.16 49.275 257.04 49.545 ;
     RECT  2.16 49.815 257.04 50.085 ;
     RECT  2.16 50.355 257.04 50.625 ;
     RECT  2.16 50.895 257.04 51.165 ;
     RECT  2.16 51.435 257.04 51.705 ;
     RECT  2.16 51.975 257.04 52.245 ;
     RECT  2.16 52.515 257.04 52.785 ;
     RECT  2.16 53.055 257.04 53.325 ;
     RECT  2.16 53.595 257.04 53.865 ;
     RECT  2.16 54.135 257.04 54.405 ;
     RECT  2.16 54.675 257.04 54.945 ;
     RECT  2.16 55.215 257.04 55.485 ;
     RECT  2.16 55.755 257.04 56.025 ;
     RECT  2.16 56.295 257.04 56.565 ;
     RECT  2.16 56.835 257.04 57.105 ;
     RECT  2.16 57.375 257.04 57.645 ;
     RECT  2.16 57.915 257.04 58.185 ;
     RECT  2.16 58.455 257.04 58.725 ;
     RECT  2.16 58.995 257.04 59.265 ;
     RECT  2.16 59.535 257.04 59.805 ;
     RECT  2.16 60.075 257.04 60.345 ;
     RECT  2.16 60.615 257.04 60.885 ;
     RECT  2.16 61.155 257.04 61.425 ;
     RECT  2.16 61.695 257.04 61.965 ;
     RECT  2.16 62.235 257.04 62.505 ;
     RECT  2.16 62.775 257.04 63.045 ;
     RECT  2.16 63.315 257.04 63.585 ;
     RECT  2.16 63.855 257.04 64.125 ;
     RECT  2.16 64.395 257.04 64.665 ;
     RECT  2.16 64.935 257.04 65.205 ;
     RECT  2.16 65.475 257.04 65.745 ;
     RECT  2.16 66.015 257.04 66.285 ;
     RECT  2.16 66.555 257.04 66.825 ;
     RECT  2.16 67.095 257.04 67.365 ;
     RECT  2.16 67.635 257.04 67.905 ;
     RECT  2.16 68.175 257.04 68.445 ;
     RECT  2.16 68.715 257.04 68.985 ;
     RECT  2.16 69.255 257.04 69.525 ;
     RECT  2.16 69.795 257.04 70.065 ;
     RECT  2.16 70.335 257.04 70.605 ;
     RECT  2.16 70.875 257.04 71.145 ;
     RECT  2.16 71.415 257.04 71.685 ;
     RECT  2.16 71.955 257.04 72.225 ;
     RECT  2.16 72.495 257.04 72.765 ;
     RECT  2.16 73.035 257.04 73.305 ;
     RECT  2.16 73.575 257.04 73.845 ;
     RECT  2.16 74.115 257.04 74.385 ;
     RECT  2.16 74.655 257.04 74.925 ;
     RECT  2.16 75.195 257.04 75.465 ;
     RECT  2.16 75.735 257.04 76.005 ;
     RECT  2.16 76.275 257.04 76.545 ;
     RECT  2.16 76.815 257.04 77.085 ;
     RECT  2.16 77.355 257.04 77.625 ;
     RECT  2.16 77.895 257.04 78.165 ;
     RECT  2.16 78.435 257.04 78.705 ;
     RECT  2.16 78.975 257.04 79.245 ;
     RECT  2.16 79.515 257.04 79.785 ;
     RECT  2.16 80.055 257.04 80.325 ;
     RECT  2.16 80.595 257.04 80.865 ;
     RECT  2.16 81.135 37.8 81.405 ;
     RECT  221.4 81.135 257.04 81.405 ;
     RECT  2.16 81.675 37.8 81.945 ;
     RECT  221.4 81.675 257.04 81.945 ;
     RECT  2.16 82.215 37.8 82.485 ;
     RECT  221.4 82.215 257.04 82.485 ;
     RECT  2.16 82.755 37.8 83.025 ;
     RECT  221.4 82.755 257.04 83.025 ;
     RECT  2.16 83.295 37.8 83.565 ;
     RECT  221.4 83.295 257.04 83.565 ;
     RECT  2.16 83.835 37.8 84.105 ;
     RECT  221.4 83.835 257.04 84.105 ;
     RECT  2.16 84.375 37.8 84.645 ;
     RECT  221.4 84.375 257.04 84.645 ;
     RECT  2.16 84.915 37.8 85.185 ;
     RECT  221.4 84.915 257.04 85.185 ;
     RECT  2.16 85.455 37.8 85.725 ;
     RECT  221.4 85.455 257.04 85.725 ;
     RECT  2.16 85.995 37.8 86.265 ;
     RECT  221.4 85.995 257.04 86.265 ;
     RECT  2.16 86.535 37.8 86.805 ;
     RECT  221.4 86.535 257.04 86.805 ;
     RECT  2.16 87.075 37.8 87.345 ;
     RECT  221.4 87.075 257.04 87.345 ;
     RECT  2.16 87.615 37.8 87.885 ;
     RECT  221.4 87.615 257.04 87.885 ;
     RECT  2.16 88.155 37.8 88.425 ;
     RECT  221.4 88.155 257.04 88.425 ;
     RECT  2.16 88.695 37.8 88.965 ;
     RECT  221.4 88.695 257.04 88.965 ;
     RECT  2.16 89.235 37.8 89.505 ;
     RECT  221.4 89.235 257.04 89.505 ;
     RECT  2.16 89.775 37.8 90.045 ;
     RECT  221.4 89.775 257.04 90.045 ;
     RECT  2.16 90.315 37.8 90.585 ;
     RECT  221.4 90.315 257.04 90.585 ;
     RECT  2.16 90.855 37.8 91.125 ;
     RECT  221.4 90.855 257.04 91.125 ;
     RECT  2.16 91.395 37.8 91.665 ;
     RECT  221.4 91.395 257.04 91.665 ;
     RECT  2.16 91.935 37.8 92.205 ;
     RECT  221.4 91.935 257.04 92.205 ;
     RECT  2.16 92.475 37.8 92.745 ;
     RECT  221.4 92.475 257.04 92.745 ;
     RECT  2.16 93.015 37.8 93.285 ;
     RECT  221.4 93.015 257.04 93.285 ;
     RECT  2.16 93.555 37.8 93.825 ;
     RECT  221.4 93.555 257.04 93.825 ;
     RECT  2.16 94.095 37.8 94.365 ;
     RECT  221.4 94.095 257.04 94.365 ;
     RECT  2.16 94.635 37.8 94.905 ;
     RECT  221.4 94.635 257.04 94.905 ;
     RECT  2.16 95.175 37.8 95.445 ;
     RECT  221.4 95.175 257.04 95.445 ;
     RECT  2.16 95.715 37.8 95.985 ;
     RECT  221.4 95.715 257.04 95.985 ;
     RECT  2.16 96.255 37.8 96.525 ;
     RECT  221.4 96.255 257.04 96.525 ;
     RECT  2.16 96.795 37.8 97.065 ;
     RECT  221.4 96.795 257.04 97.065 ;
     RECT  2.16 97.335 37.8 97.605 ;
     RECT  221.4 97.335 257.04 97.605 ;
     RECT  2.16 97.875 37.8 98.145 ;
     RECT  221.4 97.875 257.04 98.145 ;
     RECT  2.16 98.415 37.8 98.685 ;
     RECT  221.4 98.415 257.04 98.685 ;
     RECT  2.16 98.955 37.8 99.225 ;
     RECT  221.4 98.955 257.04 99.225 ;
     RECT  2.16 99.495 37.8 99.765 ;
     RECT  221.4 99.495 257.04 99.765 ;
     RECT  2.16 100.035 37.8 100.305 ;
     RECT  221.4 100.035 257.04 100.305 ;
     RECT  2.16 100.575 37.8 100.845 ;
     RECT  221.4 100.575 257.04 100.845 ;
     RECT  2.16 101.115 37.8 101.385 ;
     RECT  221.4 101.115 257.04 101.385 ;
     RECT  2.16 101.655 37.8 101.925 ;
     RECT  221.4 101.655 257.04 101.925 ;
     RECT  2.16 102.195 37.8 102.465 ;
     RECT  221.4 102.195 257.04 102.465 ;
     RECT  2.16 102.735 37.8 103.005 ;
     RECT  221.4 102.735 257.04 103.005 ;
     RECT  2.16 103.275 37.8 103.545 ;
     RECT  221.4 103.275 257.04 103.545 ;
     RECT  2.16 103.815 37.8 104.085 ;
     RECT  221.4 103.815 257.04 104.085 ;
     RECT  2.16 104.355 37.8 104.625 ;
     RECT  221.4 104.355 257.04 104.625 ;
     RECT  2.16 104.895 37.8 105.165 ;
     RECT  221.4 104.895 257.04 105.165 ;
     RECT  2.16 105.435 37.8 105.705 ;
     RECT  221.4 105.435 257.04 105.705 ;
     RECT  2.16 105.975 37.8 106.245 ;
     RECT  221.4 105.975 257.04 106.245 ;
     RECT  2.16 106.515 37.8 106.785 ;
     RECT  221.4 106.515 257.04 106.785 ;
     RECT  2.16 107.055 37.8 107.325 ;
     RECT  221.4 107.055 257.04 107.325 ;
     RECT  2.16 107.595 37.8 107.865 ;
     RECT  221.4 107.595 257.04 107.865 ;
     RECT  2.16 108.135 37.8 108.405 ;
     RECT  221.4 108.135 257.04 108.405 ;
     RECT  2.16 108.675 37.8 108.945 ;
     RECT  221.4 108.675 257.04 108.945 ;
     RECT  2.16 109.215 37.8 109.485 ;
     RECT  221.4 109.215 257.04 109.485 ;
     RECT  2.16 109.755 37.8 110.025 ;
     RECT  221.4 109.755 257.04 110.025 ;
     RECT  2.16 110.295 37.8 110.565 ;
     RECT  221.4 110.295 257.04 110.565 ;
     RECT  2.16 110.835 37.8 111.105 ;
     RECT  221.4 110.835 257.04 111.105 ;
     RECT  2.16 111.375 37.8 111.645 ;
     RECT  221.4 111.375 257.04 111.645 ;
     RECT  2.16 111.915 37.8 112.185 ;
     RECT  221.4 111.915 257.04 112.185 ;
     RECT  2.16 112.455 37.8 112.725 ;
     RECT  221.4 112.455 257.04 112.725 ;
     RECT  2.16 112.995 37.8 113.265 ;
     RECT  221.4 112.995 257.04 113.265 ;
     RECT  2.16 113.535 37.8 113.805 ;
     RECT  221.4 113.535 257.04 113.805 ;
     RECT  2.16 114.075 37.8 114.345 ;
     RECT  221.4 114.075 257.04 114.345 ;
     RECT  2.16 114.615 37.8 114.885 ;
     RECT  221.4 114.615 257.04 114.885 ;
     RECT  2.16 115.155 37.8 115.425 ;
     RECT  221.4 115.155 257.04 115.425 ;
     RECT  2.16 115.695 37.8 115.965 ;
     RECT  221.4 115.695 257.04 115.965 ;
     RECT  2.16 116.235 37.8 116.505 ;
     RECT  221.4 116.235 257.04 116.505 ;
     RECT  2.16 116.775 37.8 117.045 ;
     RECT  221.4 116.775 257.04 117.045 ;
     RECT  2.16 117.315 37.8 117.585 ;
     RECT  221.4 117.315 257.04 117.585 ;
     RECT  2.16 117.855 37.8 118.125 ;
     RECT  221.4 117.855 257.04 118.125 ;
     RECT  2.16 118.395 37.8 118.665 ;
     RECT  221.4 118.395 257.04 118.665 ;
     RECT  2.16 118.935 37.8 119.205 ;
     RECT  221.4 118.935 257.04 119.205 ;
     RECT  2.16 119.475 37.8 119.745 ;
     RECT  221.4 119.475 257.04 119.745 ;
     RECT  2.16 120.015 37.8 120.285 ;
     RECT  221.4 120.015 257.04 120.285 ;
     RECT  2.16 120.555 37.8 120.825 ;
     RECT  221.4 120.555 257.04 120.825 ;
     RECT  2.16 121.095 37.8 121.365 ;
     RECT  221.4 121.095 257.04 121.365 ;
     RECT  2.16 121.635 37.8 121.905 ;
     RECT  221.4 121.635 257.04 121.905 ;
     RECT  2.16 122.175 37.8 122.445 ;
     RECT  221.4 122.175 257.04 122.445 ;
     RECT  2.16 122.715 37.8 122.985 ;
     RECT  221.4 122.715 257.04 122.985 ;
     RECT  2.16 123.255 37.8 123.525 ;
     RECT  221.4 123.255 257.04 123.525 ;
     RECT  2.16 123.795 37.8 124.065 ;
     RECT  221.4 123.795 257.04 124.065 ;
     RECT  2.16 124.335 37.8 124.605 ;
     RECT  221.4 124.335 257.04 124.605 ;
     RECT  2.16 124.875 37.8 125.145 ;
     RECT  221.4 124.875 257.04 125.145 ;
     RECT  2.16 125.415 37.8 125.685 ;
     RECT  221.4 125.415 257.04 125.685 ;
     RECT  2.16 125.955 37.8 126.225 ;
     RECT  221.4 125.955 257.04 126.225 ;
     RECT  2.16 126.495 37.8 126.765 ;
     RECT  221.4 126.495 257.04 126.765 ;
     RECT  2.16 127.035 37.8 127.305 ;
     RECT  221.4 127.035 257.04 127.305 ;
     RECT  2.16 127.575 37.8 127.845 ;
     RECT  221.4 127.575 257.04 127.845 ;
     RECT  2.16 128.115 37.8 128.385 ;
     RECT  221.4 128.115 257.04 128.385 ;
     RECT  2.16 128.655 37.8 128.925 ;
     RECT  221.4 128.655 257.04 128.925 ;
     RECT  2.16 129.195 37.8 129.465 ;
     RECT  221.4 129.195 257.04 129.465 ;
     RECT  2.16 129.735 37.8 130.005 ;
     RECT  221.4 129.735 257.04 130.005 ;
     RECT  2.16 130.275 37.8 130.545 ;
     RECT  221.4 130.275 257.04 130.545 ;
     RECT  2.16 130.815 37.8 131.085 ;
     RECT  221.4 130.815 257.04 131.085 ;
     RECT  2.16 131.355 37.8 131.625 ;
     RECT  221.4 131.355 257.04 131.625 ;
     RECT  2.16 131.895 37.8 132.165 ;
     RECT  221.4 131.895 257.04 132.165 ;
     RECT  2.16 132.435 37.8 132.705 ;
     RECT  221.4 132.435 257.04 132.705 ;
     RECT  2.16 132.975 257.04 133.245 ;
     RECT  2.16 133.515 257.04 133.785 ;
     RECT  2.16 134.055 257.04 134.325 ;
     RECT  2.16 134.595 257.04 134.865 ;
     RECT  2.16 135.135 257.04 135.405 ;
     RECT  2.16 135.675 257.04 135.945 ;
     RECT  2.16 136.215 257.04 136.485 ;
     RECT  2.16 136.755 257.04 137.025 ;
     RECT  2.16 137.295 257.04 137.565 ;
     RECT  2.16 137.835 257.04 138.105 ;
     RECT  2.16 138.375 257.04 138.645 ;
     RECT  2.16 138.915 257.04 139.185 ;
     RECT  2.16 139.455 257.04 139.725 ;
     RECT  2.16 139.995 257.04 140.265 ;
     RECT  2.16 140.535 257.04 140.805 ;
     RECT  2.16 141.075 257.04 141.345 ;
     RECT  2.16 141.615 257.04 141.885 ;
     RECT  2.16 142.155 257.04 142.425 ;
     RECT  2.16 142.695 257.04 142.965 ;
     RECT  2.16 143.235 257.04 143.505 ;
     RECT  2.16 143.775 257.04 144.045 ;
     RECT  2.16 144.315 257.04 144.585 ;
     RECT  2.16 144.855 257.04 145.125 ;
     RECT  2.16 145.395 257.04 145.665 ;
     RECT  2.16 145.935 257.04 146.205 ;
     RECT  2.16 146.475 257.04 146.745 ;
     RECT  2.16 147.015 257.04 147.285 ;
     RECT  2.16 147.555 257.04 147.825 ;
     RECT  2.16 148.095 257.04 148.365 ;
     RECT  2.16 148.635 257.04 148.905 ;
     RECT  2.16 149.175 257.04 149.445 ;
     RECT  2.16 149.715 257.04 149.985 ;
     RECT  2.16 150.255 257.04 150.525 ;
     RECT  2.16 150.795 257.04 151.065 ;
     RECT  2.16 151.335 257.04 151.605 ;
     RECT  2.16 151.875 257.04 152.145 ;
     RECT  2.16 152.415 257.04 152.685 ;
     RECT  2.16 152.955 257.04 153.225 ;
     RECT  2.16 153.495 257.04 153.765 ;
     RECT  2.16 154.035 257.04 154.305 ;
     RECT  2.16 154.575 257.04 154.845 ;
     RECT  2.16 155.115 257.04 155.385 ;
     RECT  2.16 155.655 257.04 155.925 ;
     RECT  2.16 156.195 257.04 156.465 ;
     RECT  2.16 156.735 257.04 157.005 ;
     RECT  2.16 157.275 257.04 157.545 ;
     RECT  2.16 157.815 257.04 158.085 ;
     RECT  2.16 158.355 257.04 158.625 ;
     RECT  2.16 158.895 257.04 159.165 ;
     RECT  2.16 159.435 257.04 159.705 ;
     RECT  2.16 159.975 257.04 160.245 ;
     RECT  2.16 160.515 257.04 160.785 ;
     RECT  2.16 161.055 257.04 161.325 ;
     RECT  2.16 161.595 257.04 161.865 ;
     RECT  2.16 162.135 257.04 162.405 ;
     RECT  2.16 162.675 257.04 162.945 ;
     RECT  2.16 163.215 257.04 163.485 ;
     RECT  2.16 163.755 257.04 164.025 ;
     RECT  2.16 164.295 257.04 164.565 ;
     RECT  2.16 164.835 257.04 165.105 ;
     RECT  2.16 165.375 257.04 165.645 ;
     RECT  2.16 165.915 257.04 166.185 ;
     RECT  2.16 166.455 257.04 166.725 ;
     RECT  2.16 166.995 257.04 167.265 ;
     RECT  2.16 167.535 257.04 167.805 ;
     RECT  2.16 168.075 257.04 168.345 ;
     RECT  2.16 168.615 257.04 168.885 ;
     RECT  2.16 169.155 257.04 169.425 ;
     RECT  2.16 169.695 257.04 169.965 ;
     RECT  2.16 170.235 257.04 170.505 ;
    LAYER M1 ;
     RECT  2.16 2.151 257.04 81.009 ;
     RECT  43.2 86.4 216 127.44 ;
     RECT  2.16 81.009 37.8 132.831 ;
     RECT  221.4 81.009 257.04 132.831 ;
     RECT  2.16 132.831 257.04 170.649 ;
    LAYER M2 ;
     RECT  2.16 2.151 34.987 170.649 ;
     RECT  34.987 2.151 35.195 171 ;
     RECT  35.195 2.151 36.175 170.694 ;
     RECT  36.175 2.151 36.211 171 ;
     RECT  36.211 2.151 36.391 171.072 ;
     RECT  36.391 2.151 36.491 171.144 ;
     RECT  36.355 172.746 36.491 172.764 ;
     RECT  36.491 2.151 36.571 170.766 ;
     RECT  36.571 1.728 36.851 170.766 ;
     RECT  36.851 2.151 37.687 170.766 ;
     RECT  37.687 2.106 37.759 170.766 ;
     RECT  37.759 2.034 37.8 170.766 ;
     RECT  37.8 92.646 37.823 92.808 ;
     RECT  37.8 97.236 37.823 99.18 ;
     RECT  37.8 100.278 37.823 100.674 ;
     RECT  37.823 98.622 37.859 99.18 ;
     RECT  37.8 105.75 37.859 106.344 ;
     RECT  37.8 108.072 37.859 109.404 ;
     RECT  37.8 94.068 37.895 94.734 ;
     RECT  37.8 103.554 37.895 104.31 ;
     RECT  37.859 98.622 37.931 98.64 ;
     RECT  37.8 101.628 37.931 101.988 ;
     RECT  37.895 104.292 37.931 104.31 ;
     RECT  37.859 108.072 37.931 108.9 ;
     RECT  37.823 100.656 37.967 100.674 ;
     RECT  37.931 101.628 37.967 101.844 ;
     RECT  37.859 105.912 37.967 106.344 ;
     RECT  37.931 108.072 37.967 108.396 ;
     RECT  37.8 125.892 37.967 130.806 ;
     RECT  37.967 101.826 38.003 101.844 ;
     RECT  37.967 105.912 38.003 105.93 ;
     RECT  37.8 115.974 38.039 123.714 ;
     RECT  37.8 2.034 38.047 81.009 ;
     RECT  38.047 1.881 38.119 81.009 ;
     RECT  38.119 1.836 38.263 81.009 ;
     RECT  37.8 132.831 38.291 170.766 ;
     RECT  38.191 0.036 38.471 0.054 ;
     RECT  37.967 125.892 38.507 126.828 ;
     RECT  38.263 1.728 38.651 81.009 ;
     RECT  38.039 115.974 39.083 120.474 ;
     RECT  37.8 87.156 39.371 87.174 ;
     RECT  38.651 1.836 39.487 81.009 ;
     RECT  38.507 125.892 39.659 126.522 ;
     RECT  39.659 125.892 39.731 126.288 ;
     RECT  37.967 127.782 39.803 130.806 ;
     RECT  39.803 128.124 39.839 130.806 ;
     RECT  39.839 129.204 39.875 130.806 ;
     RECT  37.823 92.646 40.739 92.664 ;
     RECT  39.487 1.836 40.919 81.549 ;
     RECT  39.875 129.204 40.991 129.96 ;
     RECT  40.991 129.204 41.171 129.492 ;
     RECT  39.731 125.892 41.207 125.91 ;
     RECT  38.039 121.302 41.351 123.714 ;
     RECT  41.171 129.474 41.423 129.492 ;
     RECT  40.919 2.07 41.711 81.549 ;
     RECT  39.839 128.124 41.783 128.142 ;
     RECT  41.351 123.426 41.891 123.714 ;
     RECT  37.8 90.486 41.963 91.044 ;
     RECT  39.083 115.974 42.187 120.24 ;
     RECT  37.8 112.626 42.215 112.644 ;
     RECT  37.8 110.466 42.251 111.834 ;
     RECT  42.251 110.466 42.287 110.754 ;
     RECT  37.8 124.776 42.287 125.136 ;
     RECT  39.875 130.788 42.359 130.806 ;
     RECT  41.351 121.302 42.395 122.364 ;
     RECT  37.967 108.072 42.467 108.09 ;
     RECT  42.395 122.346 42.467 122.364 ;
     RECT  41.711 2.151 42.575 81.549 ;
     RECT  37.8 82.341 42.611 82.359 ;
     RECT  37.8 131.94 42.611 131.958 ;
     RECT  37.8 83.502 42.647 83.52 ;
     RECT  41.963 90.486 43.2 90.774 ;
     RECT  42.287 110.466 43.2 110.484 ;
     RECT  42.251 111.546 43.2 111.834 ;
     RECT  42.187 115.776 43.2 120.24 ;
     RECT  42.395 121.302 43.2 121.32 ;
     RECT  41.891 123.426 43.2 123.444 ;
     RECT  42.287 124.776 43.2 124.794 ;
     RECT  43.051 127.926 43.2 127.944 ;
     RECT  43.2 86.4 196.411 127.944 ;
     RECT  196.411 86.4 196.439 128.259 ;
     RECT  196.439 86.4 216 127.44 ;
     RECT  196.439 128.241 216.059 128.259 ;
     RECT  216 87.201 216.131 87.219 ;
     RECT  42.575 2.151 221.4 81.009 ;
     RECT  221.143 87.66 221.4 87.678 ;
     RECT  219.991 89.28 221.4 89.298 ;
     RECT  219.451 90.756 221.4 90.774 ;
     RECT  219.955 92.52 221.4 92.538 ;
     RECT  219.451 93.996 221.4 94.014 ;
     RECT  219.451 95.382 221.4 95.4 ;
     RECT  219.451 97.002 221.4 97.02 ;
     RECT  220.603 98.082 221.4 98.1 ;
     RECT  218.875 99.432 221.4 99.45 ;
     RECT  219.451 100.746 221.4 100.764 ;
     RECT  219.451 102.366 221.4 102.384 ;
     RECT  219.451 103.896 221.4 103.914 ;
     RECT  219.451 105.372 221.4 105.39 ;
     RECT  219.991 106.83 221.4 106.848 ;
     RECT  220.603 108.612 221.4 108.63 ;
     RECT  220.603 110.232 221.4 110.25 ;
     RECT  219.451 111.69 221.4 111.708 ;
     RECT  218.875 113.166 221.4 113.184 ;
     RECT  220.603 114.786 221.4 114.804 ;
     RECT  219.991 117.63 221.4 117.648 ;
     RECT  219.451 119.412 221.4 119.43 ;
     RECT  220.027 121.032 221.4 121.05 ;
     RECT  220.027 122.652 221.4 122.67 ;
     RECT  219.451 125.316 221.4 125.334 ;
     RECT  219.991 126.396 221.4 126.414 ;
     RECT  38.291 132.831 221.4 170.649 ;
     RECT  221.4 2.151 257.04 170.649 ;
    LAYER M3 ;
     RECT  36.558 0.012 36.612 0.031 ;
     RECT  36.63 0.012 36.684 0.031 ;
     RECT  36.702 0.012 36.756 0.031 ;
     RECT  36.774 0.012 36.828 0.031 ;
     RECT  36.846 0.012 36.9 0.031 ;
     RECT  36.918 0.012 36.972 0.031 ;
     RECT  36.99 0.012 37.044 0.031 ;
     RECT  37.062 0.012 37.116 0.031 ;
     RECT  37.134 0.012 37.188 0.031 ;
     RECT  37.206 0.012 37.26 0.031 ;
     RECT  37.278 0.012 37.332 0.031 ;
     RECT  37.35 0.012 37.404 0.031 ;
     RECT  37.422 0.012 37.476 0.031 ;
     RECT  37.494 0.012 37.548 0.031 ;
     RECT  37.566 0.012 37.62 0.031 ;
     RECT  37.638 0.012 37.692 0.031 ;
     RECT  37.71 0.012 37.764 0.031 ;
     RECT  37.782 0.012 37.836 0.031 ;
     RECT  37.854 0.012 37.908 0.031 ;
     RECT  37.926 0.012 37.98 0.031 ;
     RECT  37.998 0.012 38.052 0.031 ;
     RECT  38.07 0.012 38.124 0.031 ;
     RECT  38.142 0.012 38.196 0.031 ;
     RECT  38.214 0.012 38.268 0.031 ;
     RECT  36.558 0.031 36.612 0.037 ;
     RECT  36.63 0.031 36.684 0.037 ;
     RECT  36.702 0.031 36.756 0.037 ;
     RECT  36.774 0.031 36.828 0.037 ;
     RECT  36.846 0.031 36.9 0.037 ;
     RECT  36.918 0.031 36.972 0.037 ;
     RECT  36.99 0.031 37.044 0.037 ;
     RECT  37.062 0.031 37.116 0.037 ;
     RECT  37.134 0.031 37.188 0.037 ;
     RECT  37.206 0.031 37.26 0.037 ;
     RECT  37.278 0.031 37.332 0.037 ;
     RECT  37.35 0.031 37.404 0.037 ;
     RECT  37.422 0.031 37.476 0.037 ;
     RECT  37.494 0.031 37.548 0.037 ;
     RECT  37.566 0.031 37.62 0.037 ;
     RECT  37.638 0.031 37.692 0.037 ;
     RECT  37.71 0.031 37.764 0.037 ;
     RECT  37.782 0.031 37.836 0.037 ;
     RECT  37.854 0.031 37.908 0.037 ;
     RECT  37.926 0.031 37.98 0.037 ;
     RECT  37.998 0.031 38.052 0.037 ;
     RECT  38.07 0.031 38.124 0.037 ;
     RECT  38.142 0.031 38.196 0.037 ;
     RECT  38.214 0.031 38.268 0.037 ;
     RECT  38.286 0.031 38.466 0.037 ;
     RECT  36.54 0.037 38.466 1.723 ;
     RECT  36.54 1.723 38.646 2.029 ;
     RECT  39.96 1.957 39.978 2.029 ;
     RECT  36.54 2.029 39.978 2.101 ;
     RECT  40.896 1.831 40.914 2.101 ;
     RECT  36.54 2.101 40.914 2.219 ;
     RECT  41.688 2.065 41.706 2.219 ;
     RECT  34.815 2.143 34.905 2.263 ;
     RECT  36.54 2.219 40.77 2.263 ;
     RECT  34.815 2.263 35.19 2.371 ;
     RECT  2.415 2.143 2.505 2.413 ;
     RECT  7.815 2.143 7.905 2.413 ;
     RECT  13.215 2.143 13.305 2.413 ;
     RECT  18.615 2.143 18.705 2.413 ;
     RECT  24.015 2.143 24.105 2.413 ;
     RECT  29.415 2.143 29.505 2.413 ;
     RECT  45.615 2.143 45.705 2.413 ;
     RECT  51.015 2.143 51.105 2.413 ;
     RECT  56.415 2.143 56.505 2.413 ;
     RECT  61.815 2.143 61.905 2.413 ;
     RECT  67.215 2.143 67.305 2.413 ;
     RECT  72.615 2.143 72.705 2.413 ;
     RECT  78.015 2.143 78.105 2.413 ;
     RECT  83.415 2.143 83.505 2.413 ;
     RECT  88.815 2.143 88.905 2.413 ;
     RECT  94.215 2.143 94.305 2.413 ;
     RECT  99.615 2.143 99.705 2.413 ;
     RECT  105.015 2.143 105.105 2.413 ;
     RECT  110.415 2.143 110.505 2.413 ;
     RECT  115.815 2.143 115.905 2.413 ;
     RECT  121.215 2.143 121.305 2.413 ;
     RECT  126.615 2.143 126.705 2.413 ;
     RECT  132.015 2.143 132.105 2.413 ;
     RECT  137.415 2.143 137.505 2.413 ;
     RECT  142.815 2.143 142.905 2.413 ;
     RECT  148.215 2.143 148.305 2.413 ;
     RECT  153.615 2.143 153.705 2.413 ;
     RECT  159.015 2.143 159.105 2.413 ;
     RECT  164.415 2.143 164.505 2.413 ;
     RECT  169.815 2.143 169.905 2.413 ;
     RECT  175.215 2.143 175.305 2.413 ;
     RECT  180.615 2.143 180.705 2.413 ;
     RECT  186.015 2.143 186.105 2.413 ;
     RECT  191.415 2.143 191.505 2.413 ;
     RECT  196.815 2.143 196.905 2.413 ;
     RECT  202.215 2.143 202.305 2.413 ;
     RECT  207.615 2.143 207.705 2.413 ;
     RECT  213.015 2.143 213.105 2.413 ;
     RECT  218.415 2.143 218.505 2.413 ;
     RECT  223.815 2.143 223.905 2.413 ;
     RECT  229.215 2.143 229.305 2.413 ;
     RECT  234.615 2.143 234.705 2.413 ;
     RECT  240.015 2.143 240.105 2.413 ;
     RECT  245.415 2.143 245.505 2.413 ;
     RECT  250.815 2.143 250.905 2.413 ;
     RECT  256.215 2.143 256.305 2.413 ;
     RECT  34.815 2.371 35.55 2.605 ;
     RECT  34.815 2.605 35.622 2.731 ;
     RECT  36.396 2.263 40.77 2.731 ;
     RECT  41.652 2.263 41.67 2.759 ;
     RECT  34.815 2.731 40.77 3.145 ;
     RECT  34.815 3.145 41.346 3.721 ;
     RECT  34.815 3.721 41.886 4.225 ;
     RECT  34.815 4.225 42.462 4.531 ;
     RECT  45.615 2.413 45.897 80.747 ;
     RECT  51.015 2.413 51.297 80.747 ;
     RECT  56.415 2.413 56.697 80.747 ;
     RECT  61.815 2.413 62.097 80.747 ;
     RECT  67.215 2.413 67.497 80.747 ;
     RECT  72.615 2.413 72.897 80.747 ;
     RECT  78.015 2.413 78.297 80.747 ;
     RECT  83.415 2.413 83.697 80.747 ;
     RECT  88.815 2.413 89.097 80.747 ;
     RECT  94.215 2.413 94.497 80.747 ;
     RECT  99.615 2.413 99.897 80.747 ;
     RECT  105.015 2.413 105.297 80.747 ;
     RECT  110.415 2.413 110.697 80.747 ;
     RECT  115.815 2.413 116.097 80.747 ;
     RECT  121.215 2.413 121.497 80.747 ;
     RECT  126.615 2.413 126.897 80.747 ;
     RECT  132.015 2.413 132.297 80.747 ;
     RECT  137.415 2.413 137.697 80.747 ;
     RECT  142.815 2.413 143.097 80.747 ;
     RECT  148.215 2.413 148.497 80.747 ;
     RECT  153.615 2.413 153.897 80.747 ;
     RECT  159.015 2.413 159.297 80.747 ;
     RECT  164.415 2.413 164.697 80.747 ;
     RECT  169.815 2.413 170.097 80.747 ;
     RECT  175.215 2.413 175.497 80.747 ;
     RECT  180.615 2.413 180.897 80.747 ;
     RECT  186.015 2.413 186.297 80.747 ;
     RECT  191.415 2.413 191.697 80.747 ;
     RECT  196.815 2.413 197.097 80.747 ;
     RECT  202.215 2.413 202.497 80.747 ;
     RECT  207.615 2.413 207.897 80.747 ;
     RECT  213.015 2.413 213.297 80.747 ;
     RECT  218.415 2.413 218.697 80.747 ;
     RECT  34.815 4.531 42.534 81.017 ;
     RECT  45.615 80.747 45.705 81.017 ;
     RECT  51.015 80.747 51.105 81.017 ;
     RECT  56.415 80.747 56.505 81.017 ;
     RECT  61.815 80.747 61.905 81.017 ;
     RECT  67.215 80.747 67.305 81.017 ;
     RECT  72.615 80.747 72.705 81.017 ;
     RECT  78.015 80.747 78.105 81.017 ;
     RECT  83.415 80.747 83.505 81.017 ;
     RECT  88.815 80.747 88.905 81.017 ;
     RECT  94.215 80.747 94.305 81.017 ;
     RECT  99.615 80.747 99.705 81.017 ;
     RECT  105.015 80.747 105.105 81.017 ;
     RECT  110.415 80.747 110.505 81.017 ;
     RECT  115.815 80.747 115.905 81.017 ;
     RECT  121.215 80.747 121.305 81.017 ;
     RECT  126.615 80.747 126.705 81.017 ;
     RECT  132.015 80.747 132.105 81.017 ;
     RECT  137.415 80.747 137.505 81.017 ;
     RECT  142.815 80.747 142.905 81.017 ;
     RECT  148.215 80.747 148.305 81.017 ;
     RECT  153.615 80.747 153.705 81.017 ;
     RECT  159.015 80.747 159.105 81.017 ;
     RECT  164.415 80.747 164.505 81.017 ;
     RECT  169.815 80.747 169.905 81.017 ;
     RECT  175.215 80.747 175.305 81.017 ;
     RECT  180.615 80.747 180.705 81.017 ;
     RECT  186.015 80.747 186.105 81.017 ;
     RECT  191.415 80.747 191.505 81.017 ;
     RECT  196.815 80.747 196.905 81.017 ;
     RECT  202.215 80.747 202.305 81.017 ;
     RECT  207.615 80.747 207.705 81.017 ;
     RECT  213.015 80.747 213.105 81.017 ;
     RECT  218.415 80.747 218.505 81.017 ;
     RECT  40.68 81.017 42.534 81.526 ;
     RECT  40.68 81.526 42.57 82.336 ;
     RECT  40.68 82.336 42.606 83.497 ;
     RECT  40.68 83.497 42.642 86.4 ;
     RECT  40.68 86.4 216 87.163 ;
     RECT  40.68 87.163 216.126 87.224 ;
     RECT  221.148 87.655 221.166 87.773 ;
     RECT  34.815 81.017 39.726 88.253 ;
     RECT  34.815 88.253 36.198 88.349 ;
     RECT  36.972 88.253 39.726 88.445 ;
     RECT  35.892 88.349 36.198 88.541 ;
     RECT  36.18 88.541 36.198 88.733 ;
     RECT  37.224 88.445 39.726 89.021 ;
     RECT  219.996 89.269 220.014 89.309 ;
     RECT  38.664 89.021 39.726 89.501 ;
     RECT  40.68 87.224 216.09 89.789 ;
     RECT  39.024 89.501 39.726 89.981 ;
     RECT  41.904 89.789 216.09 90.077 ;
     RECT  39.024 89.981 39.402 90.173 ;
     RECT  41.94 90.077 216.09 90.269 ;
     RECT  39.384 90.173 39.402 90.365 ;
     RECT  40.68 89.789 40.734 90.461 ;
     RECT  42.696 90.269 216.09 90.509 ;
     RECT  42.732 90.509 216.09 90.779 ;
     RECT  219.456 90.619 219.474 90.779 ;
     RECT  41.94 90.269 41.958 91.049 ;
     RECT  219.96 92.443 219.978 92.543 ;
     RECT  40.716 90.461 40.734 92.669 ;
     RECT  37.224 89.021 37.89 93.019 ;
     RECT  36.792 93.019 37.89 93.055 ;
     RECT  219.456 93.883 219.474 94.019 ;
     RECT  36.756 93.055 37.89 94.441 ;
     RECT  36.72 94.441 37.89 94.493 ;
     RECT  219.456 95.323 219.474 95.405 ;
     RECT  36.756 94.493 37.89 95.755 ;
     RECT  36.684 95.755 37.89 96.295 ;
     RECT  36.576 96.295 37.89 96.907 ;
     RECT  36.216 96.907 37.89 96.997 ;
     RECT  219.456 96.955 219.474 97.025 ;
     RECT  220.608 98.077 220.626 98.141 ;
     RECT  36.18 96.997 37.89 98.617 ;
     RECT  36.18 98.617 37.926 98.621 ;
     RECT  218.88 99.427 218.898 99.485 ;
     RECT  36.504 98.621 37.926 99.599 ;
     RECT  36.612 99.599 37.926 100.651 ;
     RECT  219.456 100.699 219.474 100.769 ;
     RECT  36.612 100.651 37.962 101.821 ;
     RECT  36.612 101.821 37.998 102.379 ;
     RECT  219.456 102.331 219.474 102.389 ;
     RECT  36.324 102.379 37.998 102.425 ;
     RECT  36.684 102.425 37.998 103.271 ;
     RECT  36.72 103.271 37.998 103.421 ;
     RECT  36.864 103.421 37.998 104.189 ;
     RECT  219.456 103.891 219.474 104.189 ;
     RECT  36.9 104.189 37.998 104.729 ;
     RECT  219.456 104.923 219.474 105.395 ;
     RECT  36.972 104.729 37.998 105.935 ;
     RECT  219.996 106.825 220.014 107.069 ;
     RECT  36.972 105.935 37.962 108.401 ;
     RECT  220.608 108.379 220.626 108.635 ;
     RECT  36.972 108.401 37.926 108.869 ;
     RECT  37.44 108.869 37.926 108.905 ;
     RECT  37.44 108.905 37.854 109.409 ;
     RECT  220.608 110.203 220.626 110.255 ;
     RECT  42.444 108.067 42.462 110.461 ;
     RECT  43.2 90.779 216.09 110.461 ;
     RECT  37.44 109.409 37.818 110.587 ;
     RECT  42.444 110.461 216.09 110.731 ;
     RECT  42.264 110.731 216.09 111.001 ;
     RECT  36.756 110.587 37.818 111.065 ;
     RECT  36.756 111.065 36.774 111.299 ;
     RECT  219.456 111.643 219.474 111.713 ;
     RECT  36.108 111.451 36.126 111.725 ;
     RECT  37.512 111.065 37.818 111.875 ;
     RECT  42.228 111.001 216.09 112.621 ;
     RECT  42.192 112.621 216.09 112.733 ;
     RECT  37.692 111.875 37.818 112.829 ;
     RECT  42.228 112.733 216.09 113.213 ;
     RECT  218.88 113.161 218.898 113.213 ;
     RECT  37.8 112.829 37.818 113.501 ;
     RECT  40.176 113.563 40.194 113.851 ;
     RECT  41.904 113.659 41.922 114.043 ;
     RECT  42.768 113.213 216.09 114.043 ;
     RECT  40.176 113.851 40.266 114.331 ;
     RECT  39.672 114.331 40.266 114.427 ;
     RECT  39.6 114.427 40.266 114.523 ;
     RECT  220.608 114.619 220.626 114.809 ;
     RECT  37.656 113.755 37.782 115.003 ;
     RECT  39.06 114.523 40.266 115.003 ;
     RECT  41.904 114.043 216.09 115.099 ;
     RECT  37.656 115.003 40.266 115.969 ;
     RECT  221.58 116.545 221.598 116.861 ;
     RECT  37.296 115.969 40.266 117.121 ;
     RECT  219.996 117.625 220.014 117.917 ;
     RECT  219.456 119.407 219.474 119.453 ;
     RECT  37.116 117.121 40.266 119.507 ;
     RECT  37.116 119.507 40.194 119.669 ;
     RECT  37.116 119.669 39.69 120.209 ;
     RECT  36.108 120.859 36.126 121.019 ;
     RECT  220.032 120.859 220.05 121.055 ;
     RECT  37.116 120.209 39.654 121.675 ;
     RECT  36.9 121.675 39.654 122.171 ;
     RECT  41.292 115.099 216.09 122.279 ;
     RECT  36.9 122.171 39.618 122.711 ;
     RECT  220.032 122.647 220.05 122.717 ;
     RECT  41.328 122.279 216.09 122.909 ;
     RECT  36.9 122.711 39.042 123.565 ;
     RECT  41.868 122.909 216.09 123.719 ;
     RECT  221.58 123.835 221.598 124.253 ;
     RECT  42.372 123.719 216.09 125.113 ;
     RECT  219.456 125.311 219.474 125.405 ;
     RECT  36.9 123.565 39.618 126.265 ;
     RECT  42.264 125.113 216.09 126.461 ;
     RECT  219.996 126.391 220.014 126.461 ;
     RECT  42.264 126.461 216.054 127.44 ;
     RECT  36.9 126.265 39.726 127.777 ;
     RECT  42.264 127.44 43.074 127.949 ;
     RECT  41.184 125.887 41.202 128.119 ;
     RECT  42.264 127.949 42.39 128.119 ;
     RECT  196.416 127.44 196.434 128.236 ;
     RECT  196.416 128.236 196.542 128.264 ;
     RECT  216.036 127.44 216.054 128.264 ;
     RECT  36.9 127.777 39.798 128.695 ;
     RECT  41.184 128.119 42.39 129.199 ;
     RECT  36.9 128.695 39.834 129.299 ;
     RECT  36.972 129.299 39.834 129.839 ;
     RECT  41.148 129.199 42.39 129.937 ;
     RECT  37.296 129.839 39.834 130.315 ;
     RECT  40.968 129.937 42.39 131.935 ;
     RECT  37.296 130.315 39.87 131.963 ;
     RECT  37.44 131.963 39.87 132.823 ;
     RECT  40.968 131.935 42.606 132.823 ;
     RECT  196.524 128.264 196.542 132.823 ;
     RECT  37.44 132.823 42.606 132.899 ;
     RECT  196.524 132.823 196.905 132.899 ;
     RECT  45.615 132.823 45.705 133.093 ;
     RECT  51.015 132.823 51.105 133.093 ;
     RECT  56.415 132.823 56.505 133.093 ;
     RECT  61.815 132.823 61.905 133.093 ;
     RECT  67.215 132.823 67.305 133.093 ;
     RECT  72.615 132.823 72.705 133.093 ;
     RECT  78.015 132.823 78.105 133.093 ;
     RECT  83.415 132.823 83.505 133.093 ;
     RECT  88.815 132.823 88.905 133.093 ;
     RECT  94.215 132.823 94.305 133.093 ;
     RECT  99.615 132.823 99.705 133.093 ;
     RECT  105.015 132.823 105.105 133.093 ;
     RECT  110.415 132.823 110.505 133.093 ;
     RECT  115.815 132.823 115.905 133.093 ;
     RECT  121.215 132.823 121.305 133.093 ;
     RECT  126.615 132.823 126.705 133.093 ;
     RECT  132.015 132.823 132.105 133.093 ;
     RECT  137.415 132.823 137.505 133.093 ;
     RECT  142.815 132.823 142.905 133.093 ;
     RECT  148.215 132.823 148.305 133.093 ;
     RECT  153.615 132.823 153.705 133.093 ;
     RECT  159.015 132.823 159.105 133.093 ;
     RECT  164.415 132.823 164.505 133.093 ;
     RECT  169.815 132.823 169.905 133.093 ;
     RECT  175.215 132.823 175.305 133.093 ;
     RECT  180.615 132.823 180.705 133.093 ;
     RECT  186.015 132.823 186.105 133.093 ;
     RECT  191.415 132.823 191.505 133.093 ;
     RECT  196.815 132.899 196.905 133.093 ;
     RECT  202.215 132.823 202.305 133.093 ;
     RECT  207.615 132.823 207.705 133.093 ;
     RECT  213.015 132.823 213.105 133.093 ;
     RECT  218.415 132.823 218.505 133.093 ;
     RECT  37.44 132.899 42.498 133.277 ;
     RECT  37.44 133.277 38.502 134.023 ;
     RECT  37.44 134.023 38.79 134.293 ;
     RECT  37.44 134.293 38.826 134.365 ;
     RECT  39.564 133.277 42.498 134.365 ;
     RECT  37.44 134.365 42.498 134.429 ;
     RECT  37.872 134.429 42.498 134.699 ;
     RECT  37.872 134.699 37.89 134.969 ;
     RECT  38.664 134.699 42.498 135.095 ;
     RECT  38.736 135.095 42.498 135.869 ;
     RECT  38.736 135.869 42.174 136.139 ;
     RECT  38.736 136.139 42.102 141.691 ;
     RECT  38.628 141.691 42.102 142.349 ;
     RECT  38.628 142.349 41.742 142.889 ;
     RECT  38.628 142.889 41.31 148.945 ;
     RECT  38.484 148.945 41.31 149.099 ;
     RECT  38.484 149.099 41.202 149.251 ;
     RECT  36.864 149.341 36.882 149.405 ;
     RECT  38.196 149.251 41.202 149.837 ;
     RECT  37.332 149.521 37.35 150.461 ;
     RECT  38.484 149.837 41.202 152.149 ;
     RECT  38.196 152.149 41.202 152.609 ;
     RECT  38.196 152.609 41.022 155.425 ;
     RECT  37.836 155.425 41.022 155.849 ;
     RECT  37.836 155.849 40.878 156.659 ;
     RECT  37.836 156.659 40.626 158.935 ;
     RECT  37.692 158.935 40.626 159.205 ;
     RECT  37.26 159.205 40.626 160.169 ;
     RECT  37.26 160.169 40.554 162.337 ;
     RECT  37.08 162.337 40.554 163.409 ;
     RECT  37.08 163.409 40.497 164.875 ;
     RECT  36.9 164.875 40.497 165.847 ;
     RECT  36.252 165.847 40.497 166.225 ;
     RECT  34.815 88.349 35.097 167.845 ;
     RECT  36.072 166.225 40.497 167.845 ;
     RECT  34.815 167.845 40.497 169.349 ;
     RECT  39.96 169.349 40.497 169.889 ;
     RECT  34.815 169.349 39.15 170.069 ;
     RECT  34.815 170.069 38.826 170.275 ;
     RECT  34.776 170.275 38.826 170.339 ;
     RECT  2.415 2.413 2.697 170.387 ;
     RECT  7.815 2.413 8.097 170.387 ;
     RECT  13.215 2.413 13.497 170.387 ;
     RECT  18.615 2.413 18.897 170.387 ;
     RECT  24.015 2.413 24.297 170.387 ;
     RECT  29.415 2.413 29.697 170.387 ;
     RECT  40.215 169.889 40.497 170.387 ;
     RECT  45.615 133.093 45.897 170.387 ;
     RECT  51.015 133.093 51.297 170.387 ;
     RECT  56.415 133.093 56.697 170.387 ;
     RECT  61.815 133.093 62.097 170.387 ;
     RECT  67.215 133.093 67.497 170.387 ;
     RECT  72.615 133.093 72.897 170.387 ;
     RECT  78.015 133.093 78.297 170.387 ;
     RECT  83.415 133.093 83.697 170.387 ;
     RECT  88.815 133.093 89.097 170.387 ;
     RECT  94.215 133.093 94.497 170.387 ;
     RECT  99.615 133.093 99.897 170.387 ;
     RECT  105.015 133.093 105.297 170.387 ;
     RECT  110.415 133.093 110.697 170.387 ;
     RECT  115.815 133.093 116.097 170.387 ;
     RECT  121.215 133.093 121.497 170.387 ;
     RECT  126.615 133.093 126.897 170.387 ;
     RECT  132.015 133.093 132.297 170.387 ;
     RECT  137.415 133.093 137.697 170.387 ;
     RECT  142.815 133.093 143.097 170.387 ;
     RECT  148.215 133.093 148.497 170.387 ;
     RECT  153.615 133.093 153.897 170.387 ;
     RECT  159.015 133.093 159.297 170.387 ;
     RECT  164.415 133.093 164.697 170.387 ;
     RECT  169.815 133.093 170.097 170.387 ;
     RECT  175.215 133.093 175.497 170.387 ;
     RECT  180.615 133.093 180.897 170.387 ;
     RECT  186.015 133.093 186.297 170.387 ;
     RECT  191.415 133.093 191.697 170.387 ;
     RECT  196.815 133.093 197.097 170.387 ;
     RECT  202.215 133.093 202.497 170.387 ;
     RECT  207.615 133.093 207.897 170.387 ;
     RECT  213.015 133.093 213.297 170.387 ;
     RECT  218.415 133.093 218.697 170.387 ;
     RECT  223.815 2.413 224.097 170.387 ;
     RECT  229.215 2.413 229.497 170.387 ;
     RECT  234.615 2.413 234.897 170.387 ;
     RECT  240.015 2.413 240.297 170.387 ;
     RECT  245.415 2.413 245.697 170.387 ;
     RECT  250.815 2.413 251.097 170.387 ;
     RECT  256.215 2.413 256.497 170.387 ;
     RECT  34.776 170.339 38.466 170.429 ;
     RECT  34.776 170.429 38.286 170.609 ;
     RECT  2.415 170.387 2.505 170.657 ;
     RECT  7.815 170.387 7.905 170.657 ;
     RECT  13.215 170.387 13.305 170.657 ;
     RECT  18.615 170.387 18.705 170.657 ;
     RECT  24.015 170.387 24.105 170.657 ;
     RECT  29.415 170.387 29.505 170.657 ;
     RECT  34.815 170.609 38.286 170.657 ;
     RECT  40.215 170.387 40.305 170.657 ;
     RECT  45.615 170.387 45.705 170.657 ;
     RECT  51.015 170.387 51.105 170.657 ;
     RECT  56.415 170.387 56.505 170.657 ;
     RECT  61.815 170.387 61.905 170.657 ;
     RECT  67.215 170.387 67.305 170.657 ;
     RECT  72.615 170.387 72.705 170.657 ;
     RECT  78.015 170.387 78.105 170.657 ;
     RECT  83.415 170.387 83.505 170.657 ;
     RECT  88.815 170.387 88.905 170.657 ;
     RECT  94.215 170.387 94.305 170.657 ;
     RECT  99.615 170.387 99.705 170.657 ;
     RECT  105.015 170.387 105.105 170.657 ;
     RECT  110.415 170.387 110.505 170.657 ;
     RECT  115.815 170.387 115.905 170.657 ;
     RECT  121.215 170.387 121.305 170.657 ;
     RECT  126.615 170.387 126.705 170.657 ;
     RECT  132.015 170.387 132.105 170.657 ;
     RECT  137.415 170.387 137.505 170.657 ;
     RECT  142.815 170.387 142.905 170.657 ;
     RECT  148.215 170.387 148.305 170.657 ;
     RECT  153.615 170.387 153.705 170.657 ;
     RECT  159.015 170.387 159.105 170.657 ;
     RECT  164.415 170.387 164.505 170.657 ;
     RECT  169.815 170.387 169.905 170.657 ;
     RECT  175.215 170.387 175.305 170.657 ;
     RECT  180.615 170.387 180.705 170.657 ;
     RECT  186.015 170.387 186.105 170.657 ;
     RECT  191.415 170.387 191.505 170.657 ;
     RECT  196.815 170.387 196.905 170.657 ;
     RECT  202.215 170.387 202.305 170.657 ;
     RECT  207.615 170.387 207.705 170.657 ;
     RECT  213.015 170.387 213.105 170.657 ;
     RECT  218.415 170.387 218.505 170.657 ;
     RECT  223.815 170.387 223.905 170.657 ;
     RECT  229.215 170.387 229.305 170.657 ;
     RECT  234.615 170.387 234.705 170.657 ;
     RECT  240.015 170.387 240.105 170.657 ;
     RECT  245.415 170.387 245.505 170.657 ;
     RECT  250.815 170.387 250.905 170.657 ;
     RECT  256.215 170.387 256.305 170.657 ;
     RECT  34.992 170.657 38.286 170.699 ;
     RECT  34.992 170.699 37.422 170.735 ;
     RECT  38.268 170.699 38.286 170.771 ;
     RECT  34.992 170.735 36.774 171.005 ;
     RECT  35.028 171.005 36.774 172.603 ;
     RECT  34.956 172.603 36.774 172.699 ;
     RECT  34.884 172.699 36.774 172.763 ;
     RECT  34.902 172.763 34.956 172.781 ;
     RECT  34.974 172.763 35.028 172.781 ;
     RECT  35.046 172.763 35.1 172.781 ;
     RECT  35.118 172.763 35.172 172.781 ;
     RECT  35.19 172.763 35.244 172.781 ;
     RECT  35.262 172.763 35.316 172.781 ;
     RECT  35.334 172.763 35.388 172.781 ;
     RECT  35.406 172.763 35.46 172.781 ;
     RECT  35.478 172.763 35.532 172.781 ;
     RECT  35.55 172.763 35.604 172.781 ;
     RECT  35.622 172.763 35.676 172.781 ;
     RECT  35.694 172.763 35.748 172.781 ;
     RECT  35.766 172.763 35.82 172.781 ;
     RECT  35.838 172.763 35.892 172.781 ;
     RECT  35.91 172.763 35.964 172.781 ;
     RECT  35.982 172.763 36.036 172.781 ;
     RECT  36.054 172.763 36.108 172.781 ;
     RECT  36.126 172.763 36.18 172.781 ;
     RECT  36.198 172.763 36.252 172.781 ;
     RECT  36.27 172.763 36.324 172.781 ;
     RECT  36.342 172.763 36.396 172.781 ;
     RECT  36.414 172.763 36.468 172.781 ;
     RECT  36.486 172.763 36.54 172.781 ;
     RECT  36.558 172.763 36.612 172.781 ;
     RECT  36.63 172.763 36.684 172.781 ;
     RECT  36.702 172.763 36.756 172.781 ;
    LAYER M4 ;
     RECT  2.408 2.148 2.512 170.652 ;
     RECT  2.512 2.418 2.704 170.382 ;
     RECT  7.808 2.148 7.912 170.652 ;
     RECT  7.912 2.418 8.104 170.382 ;
     RECT  13.208 2.148 13.312 170.652 ;
     RECT  13.312 2.418 13.504 170.382 ;
     RECT  18.608 2.148 18.712 170.652 ;
     RECT  18.712 2.418 18.904 170.382 ;
     RECT  24.008 2.148 24.112 170.652 ;
     RECT  24.112 2.418 24.304 170.382 ;
     RECT  29.408 2.148 29.512 170.652 ;
     RECT  29.512 2.418 29.704 170.382 ;
     RECT  34.808 2.148 34.912 170.652 ;
     RECT  34.873 172.704 34.945 172.728 ;
     RECT  34.912 2.418 35.104 170.52 ;
     RECT  34.945 172.608 35.267 172.728 ;
     RECT  35.267 172.608 35.363 172.632 ;
     RECT  35.104 169.872 35.381 170.52 ;
     RECT  35.104 2.832 35.795 2.856 ;
     RECT  35.104 4.224 35.795 4.248 ;
     RECT  35.381 169.872 35.957 170.424 ;
     RECT  35.104 86.592 36.101 87.192 ;
     RECT  35.104 88.32 36.169 88.536 ;
     RECT  36.181 102.384 36.353 102.408 ;
     RECT  36.169 98.592 36.529 98.616 ;
     RECT  35.957 170.4 36.533 170.424 ;
     RECT  36.205 96.912 36.637 96.936 ;
     RECT  36.637 96.432 36.677 96.936 ;
     RECT  36.668 94.464 36.755 94.488 ;
     RECT  36.677 96.432 36.755 96.456 ;
     RECT  36.181 103.392 36.755 103.416 ;
     RECT  36.701 110.592 36.785 110.616 ;
     RECT  36.385 168.72 36.812 168.744 ;
     RECT  36.169 88.32 36.889 88.728 ;
     RECT  36.812 168 36.899 168.744 ;
     RECT  36.853 149.376 36.937 149.4 ;
     RECT  37.052 4.512 37.139 4.536 ;
     RECT  36.529 98.592 37.141 98.952 ;
     RECT  36.899 168.528 37.141 168.744 ;
     RECT  37.093 23.808 37.177 23.832 ;
     RECT  36.101 87.168 37.213 87.192 ;
     RECT  36.889 88.224 37.213 88.728 ;
     RECT  37.177 23.712 37.217 23.832 ;
     RECT  36.097 120.864 37.277 120.888 ;
     RECT  36.997 101.184 37.289 101.208 ;
     RECT  37.277 120.864 37.292 121.128 ;
     RECT  37.292 149.856 37.321 149.88 ;
     RECT  36.097 111.696 37.331 111.72 ;
     RECT  37.292 120.864 37.379 121.224 ;
     RECT  37.321 149.856 37.405 150.456 ;
     RECT  37.213 87.168 37.465 88.728 ;
     RECT  37.141 98.592 37.469 99.816 ;
     RECT  37.465 87.168 37.645 89.4 ;
     RECT  37.469 98.592 37.649 98.904 ;
     RECT  37.645 113.76 37.681 113.784 ;
     RECT  37.649 98.88 37.685 98.904 ;
     RECT  37.379 120.864 37.715 120.888 ;
     RECT  37.681 112.8 37.753 113.784 ;
     RECT  37.717 114.816 37.753 114.84 ;
     RECT  37.676 4.848 37.763 4.872 ;
     RECT  37.141 168.528 37.793 170.184 ;
     RECT  37.357 3.072 37.865 3.096 ;
     RECT  36.925 167.424 38.005 167.448 ;
     RECT  37.793 168.528 38.005 169.224 ;
     RECT  37.645 86.592 38.099 89.4 ;
     RECT  38.041 51.792 38.125 51.816 ;
     RECT  38.005 167.424 38.195 169.224 ;
     RECT  37.717 22.224 38.225 22.248 ;
     RECT  38.149 149.808 38.236 149.832 ;
     RECT  38.195 168.24 38.405 169.224 ;
     RECT  37.753 112.8 38.437 114.84 ;
     RECT  38.099 87.168 38.653 89.4 ;
     RECT  38.405 168.24 38.729 168.264 ;
     RECT  37.217 23.712 38.963 23.736 ;
     RECT  38.905 51.6 38.989 51.624 ;
     RECT  38.653 87.168 39.013 89.496 ;
     RECT  38.437 112.8 39.013 115.032 ;
     RECT  38.473 4.512 39.049 4.536 ;
     RECT  39.049 150.48 39.197 150.504 ;
     RECT  39.049 4.512 39.229 5.112 ;
     RECT  38.869 2.688 39.337 2.712 ;
     RECT  39.229 4.512 39.373 5.64 ;
     RECT  39.013 87.168 39.373 90.168 ;
     RECT  39.337 2.688 39.493 2.856 ;
     RECT  39.373 3.84 39.493 5.64 ;
     RECT  39.193 23.376 39.941 23.4 ;
     RECT  39.493 2.688 40.208 5.64 ;
     RECT  39.941 22.8 40.208 23.4 ;
     RECT  40.208 2.148 40.312 81.012 ;
     RECT  40.208 132.828 40.312 170.652 ;
     RECT  40.312 2.418 40.504 80.742 ;
     RECT  40.312 133.098 40.504 170.382 ;
     RECT  40.504 2.832 40.565 2.856 ;
     RECT  39.373 87.168 40.669 90.36 ;
     RECT  39.013 112.8 42.181 115.8 ;
     RECT  42.181 112.704 42.721 115.8 ;
     RECT  42.721 112.704 43.081 115.896 ;
     RECT  43.045 125.184 43.081 126.552 ;
     RECT  40.669 87.168 43.2 90.456 ;
     RECT  43.081 112.704 43.2 126.552 ;
     RECT  43.2 87.168 43.272 126.552 ;
     RECT  45.608 2.148 45.712 81.012 ;
     RECT  45.608 132.828 45.712 170.652 ;
     RECT  45.712 2.418 45.904 80.742 ;
     RECT  45.712 133.098 45.904 170.382 ;
     RECT  51.008 2.148 51.112 81.012 ;
     RECT  51.008 132.828 51.112 170.652 ;
     RECT  51.112 2.418 51.304 80.742 ;
     RECT  51.112 133.098 51.304 170.382 ;
     RECT  56.408 2.148 56.512 81.012 ;
     RECT  56.408 132.828 56.512 170.652 ;
     RECT  56.512 2.418 56.704 80.742 ;
     RECT  56.512 133.098 56.704 170.382 ;
     RECT  61.808 2.148 61.912 81.012 ;
     RECT  61.808 132.828 61.912 170.652 ;
     RECT  61.912 2.418 62.104 80.742 ;
     RECT  61.912 133.098 62.104 170.382 ;
     RECT  67.208 2.148 67.312 81.012 ;
     RECT  67.208 132.828 67.312 170.652 ;
     RECT  67.312 2.418 67.504 80.742 ;
     RECT  67.312 133.098 67.504 170.382 ;
     RECT  72.608 2.148 72.712 81.012 ;
     RECT  72.608 132.828 72.712 170.652 ;
     RECT  72.712 2.418 72.904 80.742 ;
     RECT  72.712 133.098 72.904 170.382 ;
     RECT  78.008 2.148 78.112 81.012 ;
     RECT  78.008 132.828 78.112 170.652 ;
     RECT  78.112 2.418 78.304 80.742 ;
     RECT  78.112 133.098 78.304 170.382 ;
     RECT  83.408 2.148 83.512 81.012 ;
     RECT  83.408 132.828 83.512 170.652 ;
     RECT  83.512 2.418 83.704 80.742 ;
     RECT  83.512 133.098 83.704 170.382 ;
     RECT  88.808 2.148 88.912 81.012 ;
     RECT  88.808 132.828 88.912 170.652 ;
     RECT  88.912 2.418 89.104 80.742 ;
     RECT  88.912 133.098 89.104 170.382 ;
     RECT  94.208 2.148 94.312 81.012 ;
     RECT  94.208 132.828 94.312 170.652 ;
     RECT  94.312 2.418 94.504 80.742 ;
     RECT  94.312 133.098 94.504 170.382 ;
     RECT  99.608 2.148 99.712 81.012 ;
     RECT  99.608 132.828 99.712 170.652 ;
     RECT  99.712 2.418 99.904 80.742 ;
     RECT  99.712 133.098 99.904 170.382 ;
     RECT  105.008 2.148 105.112 81.012 ;
     RECT  105.008 132.828 105.112 170.652 ;
     RECT  105.112 2.418 105.304 80.742 ;
     RECT  105.112 133.098 105.304 170.382 ;
     RECT  110.408 2.148 110.512 81.012 ;
     RECT  110.408 132.828 110.512 170.652 ;
     RECT  110.512 2.418 110.704 80.742 ;
     RECT  110.512 133.098 110.704 170.382 ;
     RECT  115.808 2.148 115.912 81.012 ;
     RECT  115.808 132.828 115.912 170.652 ;
     RECT  115.912 2.418 116.104 80.742 ;
     RECT  115.912 133.098 116.104 170.382 ;
     RECT  121.208 2.148 121.312 81.012 ;
     RECT  121.208 132.828 121.312 170.652 ;
     RECT  121.312 2.418 121.504 80.742 ;
     RECT  121.312 133.098 121.504 170.382 ;
     RECT  126.608 2.148 126.712 81.012 ;
     RECT  126.608 132.828 126.712 170.652 ;
     RECT  126.712 2.418 126.904 80.742 ;
     RECT  126.712 133.098 126.904 170.382 ;
     RECT  132.008 2.148 132.112 81.012 ;
     RECT  132.008 132.828 132.112 170.652 ;
     RECT  132.112 2.418 132.304 80.742 ;
     RECT  132.112 133.098 132.304 170.382 ;
     RECT  137.408 2.148 137.512 81.012 ;
     RECT  137.408 132.828 137.512 170.652 ;
     RECT  137.512 2.418 137.704 80.742 ;
     RECT  137.512 133.098 137.704 170.382 ;
     RECT  142.808 2.148 142.912 81.012 ;
     RECT  142.808 132.828 142.912 170.652 ;
     RECT  142.912 2.418 143.104 80.742 ;
     RECT  142.912 133.098 143.104 170.382 ;
     RECT  148.208 2.148 148.312 81.012 ;
     RECT  148.208 132.828 148.312 170.652 ;
     RECT  148.312 2.418 148.504 80.742 ;
     RECT  148.312 133.098 148.504 170.382 ;
     RECT  153.608 2.148 153.712 81.012 ;
     RECT  153.608 132.828 153.712 170.652 ;
     RECT  153.712 2.418 153.904 80.742 ;
     RECT  153.712 133.098 153.904 170.382 ;
     RECT  159.008 2.148 159.112 81.012 ;
     RECT  159.008 132.828 159.112 170.652 ;
     RECT  159.112 2.418 159.304 80.742 ;
     RECT  159.112 133.098 159.304 170.382 ;
     RECT  164.408 2.148 164.512 81.012 ;
     RECT  164.408 132.828 164.512 170.652 ;
     RECT  164.512 2.418 164.704 80.742 ;
     RECT  164.512 133.098 164.704 170.382 ;
     RECT  169.808 2.148 169.912 81.012 ;
     RECT  169.808 132.828 169.912 170.652 ;
     RECT  169.912 2.418 170.104 80.742 ;
     RECT  169.912 133.098 170.104 170.382 ;
     RECT  175.208 2.148 175.312 81.012 ;
     RECT  175.208 132.828 175.312 170.652 ;
     RECT  175.312 2.418 175.504 80.742 ;
     RECT  175.312 133.098 175.504 170.382 ;
     RECT  180.608 2.148 180.712 81.012 ;
     RECT  180.608 132.828 180.712 170.652 ;
     RECT  180.712 2.418 180.904 80.742 ;
     RECT  180.712 133.098 180.904 170.382 ;
     RECT  186.008 2.148 186.112 81.012 ;
     RECT  186.008 132.828 186.112 170.652 ;
     RECT  186.112 2.418 186.304 80.742 ;
     RECT  186.112 133.098 186.304 170.382 ;
     RECT  191.408 2.148 191.512 81.012 ;
     RECT  191.408 132.828 191.512 170.652 ;
     RECT  191.512 2.418 191.704 80.742 ;
     RECT  191.512 133.098 191.704 170.382 ;
     RECT  196.808 2.148 196.912 81.012 ;
     RECT  196.808 132.828 196.912 170.652 ;
     RECT  196.912 2.418 197.104 80.742 ;
     RECT  196.912 133.098 197.104 170.382 ;
     RECT  202.208 2.148 202.312 81.012 ;
     RECT  202.208 132.828 202.312 170.652 ;
     RECT  202.312 2.418 202.504 80.742 ;
     RECT  202.312 133.098 202.504 170.382 ;
     RECT  207.608 2.148 207.712 81.012 ;
     RECT  207.608 132.828 207.712 170.652 ;
     RECT  207.712 2.418 207.904 80.742 ;
     RECT  207.712 133.098 207.904 170.382 ;
     RECT  213.008 2.148 213.112 81.012 ;
     RECT  213.008 132.828 213.112 170.652 ;
     RECT  213.112 2.418 213.304 80.742 ;
     RECT  213.112 133.098 213.304 170.382 ;
     RECT  43.272 86.4 215.928 127.44 ;
     RECT  215.928 87.168 216.101 126.456 ;
     RECT  216.101 87.168 216.137 87.768 ;
     RECT  218.408 2.148 218.512 81.012 ;
     RECT  218.408 132.828 218.512 170.652 ;
     RECT  218.512 2.418 218.704 80.742 ;
     RECT  218.512 133.098 218.704 170.382 ;
     RECT  216.101 99.456 218.909 99.48 ;
     RECT  216.101 113.184 218.909 113.208 ;
     RECT  216.101 90.624 219.485 90.648 ;
     RECT  216.101 93.888 219.485 93.912 ;
     RECT  216.101 95.328 219.485 95.352 ;
     RECT  216.101 96.96 219.485 96.984 ;
     RECT  216.101 100.704 219.485 100.728 ;
     RECT  216.101 102.336 219.485 102.36 ;
     RECT  216.101 104.16 219.485 104.952 ;
     RECT  216.101 111.648 219.485 111.672 ;
     RECT  216.101 119.424 219.485 119.448 ;
     RECT  216.101 125.376 219.485 125.4 ;
     RECT  216.101 92.448 219.989 92.472 ;
     RECT  216.101 89.28 220.025 89.304 ;
     RECT  216.101 107.04 220.025 107.064 ;
     RECT  216.101 117.888 220.025 117.912 ;
     RECT  216.101 126.432 220.025 126.456 ;
     RECT  216.101 120.864 220.061 120.888 ;
     RECT  216.101 122.688 220.061 122.712 ;
     RECT  216.101 98.112 220.637 98.136 ;
     RECT  216.101 108.384 220.637 108.408 ;
     RECT  216.101 110.208 220.637 110.232 ;
     RECT  216.101 114.624 220.637 114.648 ;
     RECT  216.137 87.744 221.177 87.768 ;
     RECT  216.101 116.832 221.609 116.856 ;
     RECT  216.101 124.224 221.609 124.248 ;
     RECT  223.808 2.148 223.912 170.652 ;
     RECT  223.912 2.418 224.104 170.382 ;
     RECT  229.208 2.148 229.312 170.652 ;
     RECT  229.312 2.418 229.504 170.382 ;
     RECT  234.608 2.148 234.712 170.652 ;
     RECT  234.712 2.418 234.904 170.382 ;
     RECT  240.008 2.148 240.112 170.652 ;
     RECT  240.112 2.418 240.304 170.382 ;
     RECT  245.408 2.148 245.512 170.652 ;
     RECT  245.512 2.418 245.704 170.382 ;
     RECT  250.808 2.148 250.912 170.652 ;
     RECT  250.912 2.418 251.104 170.382 ;
     RECT  256.208 2.148 256.312 170.652 ;
     RECT  256.312 2.418 256.504 170.382 ;
    LAYER M5 ;
     RECT  2.4 2.137 2.52 2.151 ;
     RECT  7.8 2.137 7.92 2.151 ;
     RECT  13.2 2.137 13.32 2.151 ;
     RECT  18.6 2.137 18.72 2.151 ;
     RECT  24 2.137 24.12 2.151 ;
     RECT  29.4 2.137 29.52 2.151 ;
     RECT  34.8 2.137 34.92 2.151 ;
     RECT  40.2 2.137 40.32 2.151 ;
     RECT  45.6 2.137 45.72 2.151 ;
     RECT  51 2.137 51.12 2.151 ;
     RECT  56.4 2.137 56.52 2.151 ;
     RECT  61.8 2.137 61.92 2.151 ;
     RECT  67.2 2.137 67.32 2.151 ;
     RECT  72.6 2.137 72.72 2.151 ;
     RECT  78 2.137 78.12 2.151 ;
     RECT  83.4 2.137 83.52 2.151 ;
     RECT  88.8 2.137 88.92 2.151 ;
     RECT  94.2 2.137 94.32 2.151 ;
     RECT  99.6 2.137 99.72 2.151 ;
     RECT  105 2.137 105.12 2.151 ;
     RECT  110.4 2.137 110.52 2.151 ;
     RECT  115.8 2.137 115.92 2.151 ;
     RECT  121.2 2.137 121.32 2.151 ;
     RECT  126.6 2.137 126.72 2.151 ;
     RECT  132 2.137 132.12 2.151 ;
     RECT  137.4 2.137 137.52 2.151 ;
     RECT  142.8 2.137 142.92 2.151 ;
     RECT  148.2 2.137 148.32 2.151 ;
     RECT  153.6 2.137 153.72 2.151 ;
     RECT  159 2.137 159.12 2.151 ;
     RECT  164.4 2.137 164.52 2.151 ;
     RECT  169.8 2.137 169.92 2.151 ;
     RECT  175.2 2.137 175.32 2.151 ;
     RECT  180.6 2.137 180.72 2.151 ;
     RECT  186 2.137 186.12 2.151 ;
     RECT  191.4 2.137 191.52 2.151 ;
     RECT  196.8 2.137 196.92 2.151 ;
     RECT  202.2 2.137 202.32 2.151 ;
     RECT  207.6 2.137 207.72 2.151 ;
     RECT  213 2.137 213.12 2.151 ;
     RECT  218.4 2.137 218.52 2.151 ;
     RECT  223.8 2.137 223.92 2.151 ;
     RECT  229.2 2.137 229.32 2.151 ;
     RECT  234.6 2.137 234.72 2.151 ;
     RECT  240 2.137 240.12 2.151 ;
     RECT  245.4 2.137 245.52 2.151 ;
     RECT  250.8 2.137 250.92 2.151 ;
     RECT  256.2 2.137 256.32 2.151 ;
     RECT  40.2 2.151 40.512 2.677 ;
     RECT  34.8 2.151 35.112 2.821 ;
     RECT  39.6 2.677 40.512 3.733 ;
     RECT  34.8 2.821 35.784 4.259 ;
     RECT  37.104 4.501 37.128 4.837 ;
     RECT  39.504 3.733 40.512 5.123 ;
     RECT  37.104 4.837 37.752 22.259 ;
     RECT  39.984 5.123 40.512 22.835 ;
     RECT  40.08 22.835 40.512 23.411 ;
     RECT  37.104 22.259 37.128 23.843 ;
     RECT  38.928 23.701 38.952 51.635 ;
     RECT  34.8 4.259 35.112 86.581 ;
     RECT  38.064 51.781 38.088 86.581 ;
     RECT  37.68 86.581 38.088 86.627 ;
     RECT  34.8 86.581 35.256 87.157 ;
     RECT  37.68 86.627 37.704 94.453 ;
     RECT  36.72 94.453 37.704 96.467 ;
     RECT  34.8 87.157 35.352 98.581 ;
     RECT  34.8 98.581 36.216 103.381 ;
     RECT  37.68 96.467 37.704 103.381 ;
     RECT  34.8 103.381 37.704 103.427 ;
     RECT  36.72 103.427 37.704 110.627 ;
     RECT  37.68 110.627 37.704 111.685 ;
     RECT  37.296 111.685 37.704 120.899 ;
     RECT  37.296 120.899 37.368 121.139 ;
     RECT  37.344 121.139 37.368 149.365 ;
     RECT  36.864 149.365 37.368 149.797 ;
     RECT  36.864 149.797 38.184 168.035 ;
     RECT  37.344 168.035 38.184 168.275 ;
     RECT  37.344 168.275 37.368 170.195 ;
     RECT  2.4 2.151 2.712 170.649 ;
     RECT  7.8 2.151 8.112 170.649 ;
     RECT  13.2 2.151 13.512 170.649 ;
     RECT  18.6 2.151 18.912 170.649 ;
     RECT  24 2.151 24.312 170.649 ;
     RECT  29.4 2.151 29.712 170.649 ;
     RECT  40.2 23.411 40.512 170.649 ;
     RECT  45.6 2.151 45.912 170.649 ;
     RECT  51 2.151 51.312 170.649 ;
     RECT  56.4 2.151 56.712 170.649 ;
     RECT  61.8 2.151 62.112 170.649 ;
     RECT  67.2 2.151 67.512 170.649 ;
     RECT  72.6 2.151 72.912 170.649 ;
     RECT  78 2.151 78.312 170.649 ;
     RECT  83.4 2.151 83.712 170.649 ;
     RECT  88.8 2.151 89.112 170.649 ;
     RECT  94.2 2.151 94.512 170.649 ;
     RECT  99.6 2.151 99.912 170.649 ;
     RECT  105 2.151 105.312 170.649 ;
     RECT  110.4 2.151 110.712 170.649 ;
     RECT  115.8 2.151 116.112 170.649 ;
     RECT  121.2 2.151 121.512 170.649 ;
     RECT  126.6 2.151 126.912 170.649 ;
     RECT  132 2.151 132.312 170.649 ;
     RECT  137.4 2.151 137.712 170.649 ;
     RECT  142.8 2.151 143.112 170.649 ;
     RECT  148.2 2.151 148.512 170.649 ;
     RECT  153.6 2.151 153.912 170.649 ;
     RECT  159 2.151 159.312 170.649 ;
     RECT  164.4 2.151 164.712 170.649 ;
     RECT  169.8 2.151 170.112 170.649 ;
     RECT  175.2 2.151 175.512 170.649 ;
     RECT  180.6 2.151 180.912 170.649 ;
     RECT  186 2.151 186.312 170.649 ;
     RECT  191.4 2.151 191.712 170.649 ;
     RECT  196.8 2.151 197.112 170.649 ;
     RECT  202.2 2.151 202.512 170.649 ;
     RECT  207.6 2.151 207.912 170.649 ;
     RECT  213 2.151 213.312 170.649 ;
     RECT  218.4 2.151 218.712 170.649 ;
     RECT  223.8 2.151 224.112 170.649 ;
     RECT  229.2 2.151 229.512 170.649 ;
     RECT  234.6 2.151 234.912 170.649 ;
     RECT  240 2.151 240.312 170.649 ;
     RECT  245.4 2.151 245.712 170.649 ;
     RECT  250.8 2.151 251.112 170.649 ;
     RECT  256.2 2.151 256.512 170.649 ;
     RECT  2.4 170.649 2.52 170.663 ;
     RECT  7.8 170.649 7.92 170.663 ;
     RECT  13.2 170.649 13.32 170.663 ;
     RECT  18.6 170.649 18.72 170.663 ;
     RECT  24 170.649 24.12 170.663 ;
     RECT  29.4 170.649 29.52 170.663 ;
     RECT  34.8 103.427 35.352 170.663 ;
     RECT  40.2 170.649 40.32 170.663 ;
     RECT  45.6 170.649 45.72 170.663 ;
     RECT  51 170.649 51.12 170.663 ;
     RECT  56.4 170.649 56.52 170.663 ;
     RECT  61.8 170.649 61.92 170.663 ;
     RECT  67.2 170.649 67.32 170.663 ;
     RECT  72.6 170.649 72.72 170.663 ;
     RECT  78 170.649 78.12 170.663 ;
     RECT  83.4 170.649 83.52 170.663 ;
     RECT  88.8 170.649 88.92 170.663 ;
     RECT  94.2 170.649 94.32 170.663 ;
     RECT  99.6 170.649 99.72 170.663 ;
     RECT  105 170.649 105.12 170.663 ;
     RECT  110.4 170.649 110.52 170.663 ;
     RECT  115.8 170.649 115.92 170.663 ;
     RECT  121.2 170.649 121.32 170.663 ;
     RECT  126.6 170.649 126.72 170.663 ;
     RECT  132 170.649 132.12 170.663 ;
     RECT  137.4 170.649 137.52 170.663 ;
     RECT  142.8 170.649 142.92 170.663 ;
     RECT  148.2 170.649 148.32 170.663 ;
     RECT  153.6 170.649 153.72 170.663 ;
     RECT  159 170.649 159.12 170.663 ;
     RECT  164.4 170.649 164.52 170.663 ;
     RECT  169.8 170.649 169.92 170.663 ;
     RECT  175.2 170.649 175.32 170.663 ;
     RECT  180.6 170.649 180.72 170.663 ;
     RECT  186 170.649 186.12 170.663 ;
     RECT  191.4 170.649 191.52 170.663 ;
     RECT  196.8 170.649 196.92 170.663 ;
     RECT  202.2 170.649 202.32 170.663 ;
     RECT  207.6 170.649 207.72 170.663 ;
     RECT  213 170.649 213.12 170.663 ;
     RECT  218.4 170.649 218.52 170.663 ;
     RECT  223.8 170.649 223.92 170.663 ;
     RECT  229.2 170.649 229.32 170.663 ;
     RECT  234.6 170.649 234.72 170.663 ;
     RECT  240 170.649 240.12 170.663 ;
     RECT  245.4 170.649 245.52 170.663 ;
     RECT  250.8 170.649 250.92 170.663 ;
     RECT  256.2 170.649 256.32 170.663 ;
     RECT  35.232 170.663 35.352 172.643 ;
     RECT  35.232 172.643 35.256 172.739 ;
     RECT  39.984 22.835 40.08 23.411 ;
     RECT  39.984 23.411 40.2 23.701 ;
     RECT  38.952 23.701 40.2 51.635 ;
     RECT  35.352 94.453 36.72 96.467 ;
     RECT  36.216 98.581 37.68 103.381 ;
     RECT  35.352 103.427 36.72 110.627 ;
     RECT  37.296 110.627 37.68 111.685 ;
     RECT  35.352 149.365 36.864 168.035 ;
  END
END ot_hidx_meta_sram146
END LIBRARY
